VERSION 5.8 ;
BUSBITCHARS "[]" ;
DIVIDERCHAR "/" ;
UNITS
    DATABASE MICRONS 1000 ;
END UNITS

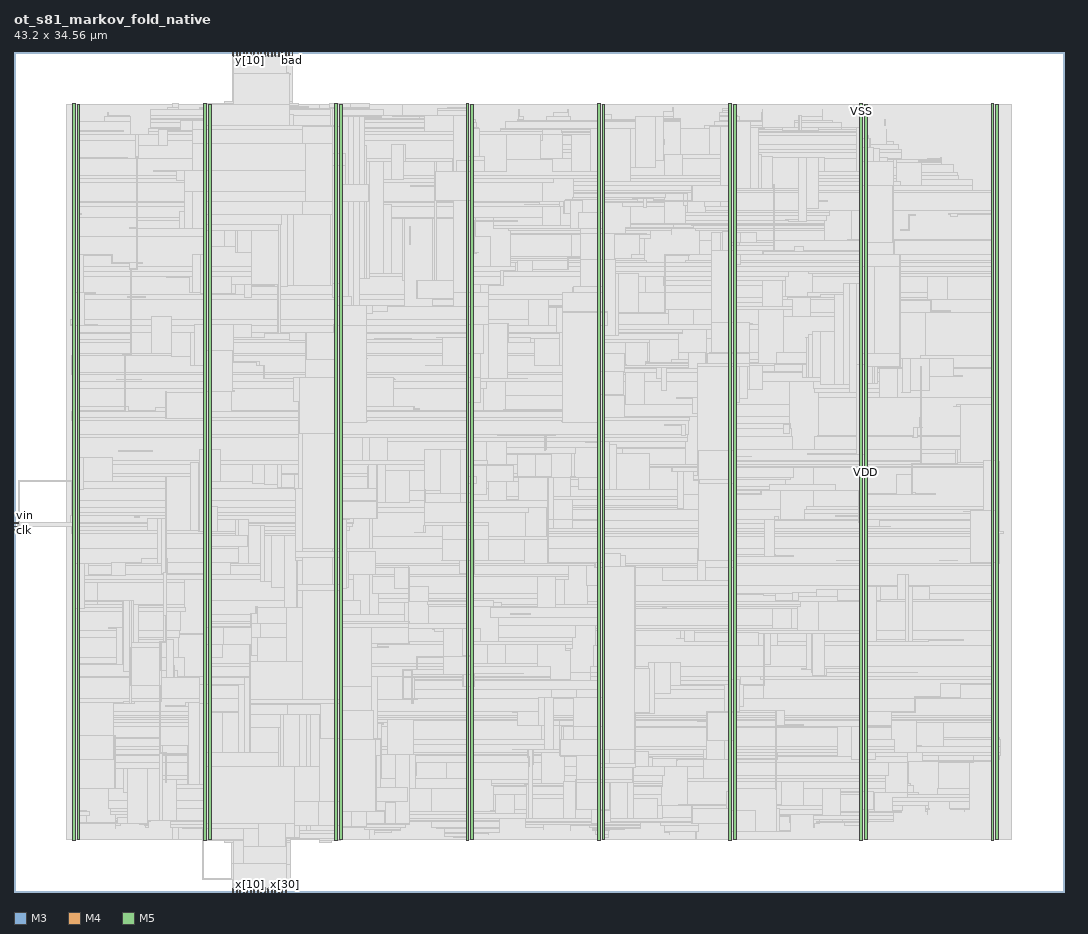
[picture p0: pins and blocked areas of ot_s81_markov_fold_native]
MACRO ot_s81_markov_fold_native
  FOREIGN ot_s81_markov_fold_native 0 0 ;
  CLASS BLOCK ;
  SIZE 43.2 BY 34.56 ;
  PIN bad
    DIRECTION OUTPUT ;
    USE SIGNAL ;
    PORT
      LAYER M3 ;
        RECT  11.448 34.416 11.466 34.56 ;
    END
  END bad
  PIN clk
    DIRECTION INPUT ;
    USE SIGNAL ;
    PORT
      LAYER M4 ;
        RECT  0 14.88 0.192 14.904 ;
    END
  END clk
  PIN rst_n
    DIRECTION INPUT ;
    USE SIGNAL ;
    PORT
      LAYER M4 ;
        RECT  0 15.024 0.192 15.048 ;
    END
  END rst_n
  PIN vin
    DIRECTION INPUT ;
    USE SIGNAL ;
    PORT
      LAYER M4 ;
        RECT  0 15.168 0.192 15.192 ;
    END
  END vin
  PIN vout
    DIRECTION OUTPUT ;
    USE SIGNAL ;
    PORT
      LAYER M3 ;
        RECT  11.304 34.416 11.322 34.56 ;
    END
  END vout
  PIN x[0]
    DIRECTION INPUT ;
    USE SIGNAL ;
    PORT
      LAYER M3 ;
        RECT  9 0 9.018 0.144 ;
    END
  END x[0]
  PIN x[10]
    DIRECTION INPUT ;
    USE SIGNAL ;
    PORT
      LAYER M3 ;
        RECT  9.72 0 9.738 0.144 ;
    END
  END x[10]
  PIN x[11]
    DIRECTION INPUT ;
    USE SIGNAL ;
    PORT
      LAYER M5 ;
        RECT  9.744 0 9.768 0.192 ;
    END
  END x[11]
  PIN x[12]
    DIRECTION INPUT ;
    USE SIGNAL ;
    PORT
      LAYER M3 ;
        RECT  9.864 0 9.882 0.144 ;
    END
  END x[12]
  PIN x[13]
    DIRECTION INPUT ;
    USE SIGNAL ;
    PORT
      LAYER M5 ;
        RECT  9.888 0 9.912 0.192 ;
    END
  END x[13]
  PIN x[14]
    DIRECTION INPUT ;
    USE SIGNAL ;
    PORT
      LAYER M3 ;
        RECT  10.008 0 10.026 0.144 ;
    END
  END x[14]
  PIN x[15]
    DIRECTION INPUT ;
    USE SIGNAL ;
    PORT
      LAYER M5 ;
        RECT  10.032 0 10.056 0.192 ;
    END
  END x[15]
  PIN x[16]
    DIRECTION INPUT ;
    USE SIGNAL ;
    PORT
      LAYER M3 ;
        RECT  10.152 0 10.17 0.144 ;
    END
  END x[16]
  PIN x[17]
    DIRECTION INPUT ;
    USE SIGNAL ;
    PORT
      LAYER M5 ;
        RECT  10.176 0 10.2 0.192 ;
    END
  END x[17]
  PIN x[18]
    DIRECTION INPUT ;
    USE SIGNAL ;
    PORT
      LAYER M3 ;
        RECT  10.296 0 10.314 0.144 ;
    END
  END x[18]
  PIN x[19]
    DIRECTION INPUT ;
    USE SIGNAL ;
    PORT
      LAYER M5 ;
        RECT  10.32 0 10.344 0.192 ;
    END
  END x[19]
  PIN x[1]
    DIRECTION INPUT ;
    USE SIGNAL ;
    PORT
      LAYER M5 ;
        RECT  9.024 0 9.048 0.192 ;
    END
  END x[1]
  PIN x[20]
    DIRECTION INPUT ;
    USE SIGNAL ;
    PORT
      LAYER M3 ;
        RECT  10.44 0 10.458 0.144 ;
    END
  END x[20]
  PIN x[21]
    DIRECTION INPUT ;
    USE SIGNAL ;
    PORT
      LAYER M5 ;
        RECT  10.464 0 10.488 0.192 ;
    END
  END x[21]
  PIN x[22]
    DIRECTION INPUT ;
    USE SIGNAL ;
    PORT
      LAYER M3 ;
        RECT  10.584 0 10.602 0.144 ;
    END
  END x[22]
  PIN x[23]
    DIRECTION INPUT ;
    USE SIGNAL ;
    PORT
      LAYER M5 ;
        RECT  10.608 0 10.632 0.192 ;
    END
  END x[23]
  PIN x[24]
    DIRECTION INPUT ;
    USE SIGNAL ;
    PORT
      LAYER M3 ;
        RECT  10.728 0 10.746 0.144 ;
    END
  END x[24]
  PIN x[25]
    DIRECTION INPUT ;
    USE SIGNAL ;
    PORT
      LAYER M5 ;
        RECT  10.752 0 10.776 0.192 ;
    END
  END x[25]
  PIN x[26]
    DIRECTION INPUT ;
    USE SIGNAL ;
    PORT
      LAYER M3 ;
        RECT  10.872 0 10.89 0.144 ;
    END
  END x[26]
  PIN x[27]
    DIRECTION INPUT ;
    USE SIGNAL ;
    PORT
      LAYER M5 ;
        RECT  10.896 0 10.92 0.192 ;
    END
  END x[27]
  PIN x[28]
    DIRECTION INPUT ;
    USE SIGNAL ;
    PORT
      LAYER M3 ;
        RECT  11.016 0 11.034 0.144 ;
    END
  END x[28]
  PIN x[29]
    DIRECTION INPUT ;
    USE SIGNAL ;
    PORT
      LAYER M5 ;
        RECT  11.04 0 11.064 0.192 ;
    END
  END x[29]
  PIN x[2]
    DIRECTION INPUT ;
    USE SIGNAL ;
    PORT
      LAYER M3 ;
        RECT  9.144 0 9.162 0.144 ;
    END
  END x[2]
  PIN x[30]
    DIRECTION INPUT ;
    USE SIGNAL ;
    PORT
      LAYER M3 ;
        RECT  11.16 0 11.178 0.144 ;
    END
  END x[30]
  PIN x[31]
    DIRECTION INPUT ;
    USE SIGNAL ;
    PORT
      LAYER M5 ;
        RECT  11.184 0 11.208 0.192 ;
    END
  END x[31]
  PIN x[3]
    DIRECTION INPUT ;
    USE SIGNAL ;
    PORT
      LAYER M5 ;
        RECT  9.168 0 9.192 0.192 ;
    END
  END x[3]
  PIN x[4]
    DIRECTION INPUT ;
    USE SIGNAL ;
    PORT
      LAYER M3 ;
        RECT  9.288 0 9.306 0.144 ;
    END
  END x[4]
  PIN x[5]
    DIRECTION INPUT ;
    USE SIGNAL ;
    PORT
      LAYER M5 ;
        RECT  9.312 0 9.336 0.192 ;
    END
  END x[5]
  PIN x[6]
    DIRECTION INPUT ;
    USE SIGNAL ;
    PORT
      LAYER M3 ;
        RECT  9.432 0 9.45 0.144 ;
    END
  END x[6]
  PIN x[7]
    DIRECTION INPUT ;
    USE SIGNAL ;
    PORT
      LAYER M5 ;
        RECT  9.456 0 9.48 0.192 ;
    END
  END x[7]
  PIN x[8]
    DIRECTION INPUT ;
    USE SIGNAL ;
    PORT
      LAYER M3 ;
        RECT  9.576 0 9.594 0.144 ;
    END
  END x[8]
  PIN x[9]
    DIRECTION INPUT ;
    USE SIGNAL ;
    PORT
      LAYER M5 ;
        RECT  9.6 0 9.624 0.192 ;
    END
  END x[9]
  PIN y[0]
    DIRECTION OUTPUT ;
    USE SIGNAL ;
    PORT
      LAYER M3 ;
        RECT  9 34.416 9.018 34.56 ;
    END
  END y[0]
  PIN y[10]
    DIRECTION OUTPUT ;
    USE SIGNAL ;
    PORT
      LAYER M3 ;
        RECT  9.72 34.416 9.738 34.56 ;
    END
  END y[10]
  PIN y[11]
    DIRECTION OUTPUT ;
    USE SIGNAL ;
    PORT
      LAYER M5 ;
        RECT  9.744 34.368 9.768 34.56 ;
    END
  END y[11]
  PIN y[12]
    DIRECTION OUTPUT ;
    USE SIGNAL ;
    PORT
      LAYER M3 ;
        RECT  9.864 34.416 9.882 34.56 ;
    END
  END y[12]
  PIN y[13]
    DIRECTION OUTPUT ;
    USE SIGNAL ;
    PORT
      LAYER M5 ;
        RECT  9.888 34.368 9.912 34.56 ;
    END
  END y[13]
  PIN y[14]
    DIRECTION OUTPUT ;
    USE SIGNAL ;
    PORT
      LAYER M3 ;
        RECT  10.008 34.416 10.026 34.56 ;
    END
  END y[14]
  PIN y[15]
    DIRECTION OUTPUT ;
    USE SIGNAL ;
    PORT
      LAYER M5 ;
        RECT  10.032 34.368 10.056 34.56 ;
    END
  END y[15]
  PIN y[16]
    DIRECTION OUTPUT ;
    USE SIGNAL ;
    PORT
      LAYER M3 ;
        RECT  10.152 34.416 10.17 34.56 ;
    END
  END y[16]
  PIN y[17]
    DIRECTION OUTPUT ;
    USE SIGNAL ;
    PORT
      LAYER M5 ;
        RECT  10.176 34.368 10.2 34.56 ;
    END
  END y[17]
  PIN y[18]
    DIRECTION OUTPUT ;
    USE SIGNAL ;
    PORT
      LAYER M3 ;
        RECT  10.296 34.416 10.314 34.56 ;
    END
  END y[18]
  PIN y[19]
    DIRECTION OUTPUT ;
    USE SIGNAL ;
    PORT
      LAYER M5 ;
        RECT  10.32 34.368 10.344 34.56 ;
    END
  END y[19]
  PIN y[1]
    DIRECTION OUTPUT ;
    USE SIGNAL ;
    PORT
      LAYER M5 ;
        RECT  9.024 34.368 9.048 34.56 ;
    END
  END y[1]
  PIN y[20]
    DIRECTION OUTPUT ;
    USE SIGNAL ;
    PORT
      LAYER M3 ;
        RECT  10.44 34.416 10.458 34.56 ;
    END
  END y[20]
  PIN y[21]
    DIRECTION OUTPUT ;
    USE SIGNAL ;
    PORT
      LAYER M5 ;
        RECT  10.464 34.368 10.488 34.56 ;
    END
  END y[21]
  PIN y[22]
    DIRECTION OUTPUT ;
    USE SIGNAL ;
    PORT
      LAYER M3 ;
        RECT  10.584 34.416 10.602 34.56 ;
    END
  END y[22]
  PIN y[23]
    DIRECTION OUTPUT ;
    USE SIGNAL ;
    PORT
      LAYER M5 ;
        RECT  10.608 34.368 10.632 34.56 ;
    END
  END y[23]
  PIN y[24]
    DIRECTION OUTPUT ;
    USE SIGNAL ;
    PORT
      LAYER M3 ;
        RECT  10.728 34.416 10.746 34.56 ;
    END
  END y[24]
  PIN y[25]
    DIRECTION OUTPUT ;
    USE SIGNAL ;
    PORT
      LAYER M5 ;
        RECT  10.752 34.368 10.776 34.56 ;
    END
  END y[25]
  PIN y[26]
    DIRECTION OUTPUT ;
    USE SIGNAL ;
    PORT
      LAYER M3 ;
        RECT  10.872 34.416 10.89 34.56 ;
    END
  END y[26]
  PIN y[27]
    DIRECTION OUTPUT ;
    USE SIGNAL ;
    PORT
      LAYER M5 ;
        RECT  10.896 34.368 10.92 34.56 ;
    END
  END y[27]
  PIN y[28]
    DIRECTION OUTPUT ;
    USE SIGNAL ;
    PORT
      LAYER M3 ;
        RECT  11.016 34.416 11.034 34.56 ;
    END
  END y[28]
  PIN y[29]
    DIRECTION OUTPUT ;
    USE SIGNAL ;
    PORT
      LAYER M5 ;
        RECT  11.04 34.368 11.064 34.56 ;
    END
  END y[29]
  PIN y[2]
    DIRECTION OUTPUT ;
    USE SIGNAL ;
    PORT
      LAYER M3 ;
        RECT  9.144 34.416 9.162 34.56 ;
    END
  END y[2]
  PIN y[30]
    DIRECTION OUTPUT ;
    USE SIGNAL ;
    PORT
      LAYER M3 ;
        RECT  11.16 34.416 11.178 34.56 ;
    END
  END y[30]
  PIN y[31]
    DIRECTION OUTPUT ;
    USE SIGNAL ;
    PORT
      LAYER M5 ;
        RECT  11.184 34.368 11.208 34.56 ;
    END
  END y[31]
  PIN y[3]
    DIRECTION OUTPUT ;
    USE SIGNAL ;
    PORT
      LAYER M5 ;
        RECT  9.168 34.368 9.192 34.56 ;
    END
  END y[3]
  PIN y[4]
    DIRECTION OUTPUT ;
    USE SIGNAL ;
    PORT
      LAYER M3 ;
        RECT  9.288 34.416 9.306 34.56 ;
    END
  END y[4]
  PIN y[5]
    DIRECTION OUTPUT ;
    USE SIGNAL ;
    PORT
      LAYER M5 ;
        RECT  9.312 34.368 9.336 34.56 ;
    END
  END y[5]
  PIN y[6]
    DIRECTION OUTPUT ;
    USE SIGNAL ;
    PORT
      LAYER M3 ;
        RECT  9.432 34.416 9.45 34.56 ;
    END
  END y[6]
  PIN y[7]
    DIRECTION OUTPUT ;
    USE SIGNAL ;
    PORT
      LAYER M5 ;
        RECT  9.456 34.368 9.48 34.56 ;
    END
  END y[7]
  PIN y[8]
    DIRECTION OUTPUT ;
    USE SIGNAL ;
    PORT
      LAYER M3 ;
        RECT  9.576 34.416 9.594 34.56 ;
    END
  END y[8]
  PIN y[9]
    DIRECTION OUTPUT ;
    USE SIGNAL ;
    PORT
      LAYER M5 ;
        RECT  9.6 34.368 9.624 34.56 ;
    END
  END y[9]
  PIN VDD
    DIRECTION INOUT ;
    USE POWER ;
    PORT
      LAYER M5 ;
        RECT  40.392 2.151 40.512 32.409 ;
        RECT  34.992 2.151 35.112 32.409 ;
        RECT  29.592 2.151 29.712 32.409 ;
        RECT  24.192 2.151 24.312 32.409 ;
        RECT  18.792 2.151 18.912 32.409 ;
        RECT  13.392 2.151 13.512 32.409 ;
        RECT  7.992 2.151 8.112 32.409 ;
        RECT  2.592 2.151 2.712 32.409 ;
    END
  END VDD
  PIN VSS
    DIRECTION INOUT ;
    USE GROUND ;
    PORT
      LAYER M5 ;
        RECT  40.2 2.137 40.32 32.423 ;
        RECT  34.8 2.137 34.92 32.423 ;
        RECT  29.4 2.137 29.52 32.423 ;
        RECT  24 2.137 24.12 32.423 ;
        RECT  18.6 2.137 18.72 32.423 ;
        RECT  13.2 2.137 13.32 32.423 ;
        RECT  7.8 2.137 7.92 32.423 ;
        RECT  2.4 2.137 2.52 32.423 ;
    END
  END VSS
  # OT_OBS_CLOSED layer=M5 d_um=1.536 added=71
  OBS
    LAYER RVTN ;
     RECT  2.16 2.16 41.04 2.295 ;
     RECT  2.16 2.565 41.04 2.835 ;
     RECT  2.16 3.105 41.04 3.375 ;
     RECT  2.16 3.645 41.04 3.915 ;
     RECT  2.16 4.185 41.04 4.455 ;
     RECT  2.16 4.725 41.04 4.995 ;
     RECT  2.16 5.265 41.04 5.535 ;
     RECT  2.16 5.805 41.04 6.075 ;
     RECT  2.16 6.345 41.04 6.615 ;
     RECT  2.16 6.885 41.04 7.155 ;
     RECT  2.16 7.425 41.04 7.695 ;
     RECT  2.16 7.965 41.04 8.235 ;
     RECT  2.16 8.505 41.04 8.775 ;
     RECT  2.16 9.045 41.04 9.315 ;
     RECT  2.16 9.585 41.04 9.855 ;
     RECT  2.16 10.125 41.04 10.395 ;
     RECT  2.16 10.665 41.04 10.935 ;
     RECT  2.16 11.205 41.04 11.475 ;
     RECT  2.16 11.745 41.04 12.015 ;
     RECT  2.16 12.285 41.04 12.555 ;
     RECT  2.16 12.825 41.04 13.095 ;
     RECT  2.16 13.365 41.04 13.635 ;
     RECT  2.16 13.905 41.04 14.175 ;
     RECT  2.16 14.445 41.04 14.715 ;
     RECT  2.16 14.985 41.04 15.255 ;
     RECT  2.16 15.525 41.04 15.795 ;
     RECT  2.16 16.065 41.04 16.335 ;
     RECT  2.16 16.605 41.04 16.875 ;
     RECT  2.16 17.145 41.04 17.415 ;
     RECT  2.16 17.685 41.04 17.955 ;
     RECT  2.16 18.225 41.04 18.495 ;
     RECT  2.16 18.765 41.04 19.035 ;
     RECT  2.16 19.305 41.04 19.575 ;
     RECT  2.16 19.845 41.04 20.115 ;
     RECT  2.16 20.385 41.04 20.655 ;
     RECT  2.16 20.925 41.04 21.195 ;
     RECT  2.16 21.465 41.04 21.735 ;
     RECT  2.16 22.005 41.04 22.275 ;
     RECT  2.16 22.545 41.04 22.815 ;
     RECT  2.16 23.085 41.04 23.355 ;
     RECT  2.16 23.625 41.04 23.895 ;
     RECT  2.16 24.165 41.04 24.435 ;
     RECT  2.16 24.705 41.04 24.975 ;
     RECT  2.16 25.245 41.04 25.515 ;
     RECT  2.16 25.785 41.04 26.055 ;
     RECT  2.16 26.325 41.04 26.595 ;
     RECT  2.16 26.865 41.04 27.135 ;
     RECT  2.16 27.405 41.04 27.675 ;
     RECT  2.16 27.945 41.04 28.215 ;
     RECT  2.16 28.485 41.04 28.755 ;
     RECT  2.16 29.025 41.04 29.295 ;
     RECT  2.16 29.565 41.04 29.835 ;
     RECT  2.16 30.105 41.04 30.375 ;
     RECT  2.16 30.645 41.04 30.915 ;
     RECT  2.16 31.185 41.04 31.455 ;
     RECT  2.16 31.725 41.04 31.995 ;
     RECT  2.16 32.265 41.04 32.4 ;
    LAYER RVTP ;
     RECT  2.16 2.295 41.04 2.565 ;
     RECT  2.16 2.835 41.04 3.105 ;
     RECT  2.16 3.375 41.04 3.645 ;
     RECT  2.16 3.915 41.04 4.185 ;
     RECT  2.16 4.455 41.04 4.725 ;
     RECT  2.16 4.995 41.04 5.265 ;
     RECT  2.16 5.535 41.04 5.805 ;
     RECT  2.16 6.075 41.04 6.345 ;
     RECT  2.16 6.615 41.04 6.885 ;
     RECT  2.16 7.155 41.04 7.425 ;
     RECT  2.16 7.695 41.04 7.965 ;
     RECT  2.16 8.235 41.04 8.505 ;
     RECT  2.16 8.775 41.04 9.045 ;
     RECT  2.16 9.315 41.04 9.585 ;
     RECT  2.16 9.855 41.04 10.125 ;
     RECT  2.16 10.395 41.04 10.665 ;
     RECT  2.16 10.935 41.04 11.205 ;
     RECT  2.16 11.475 41.04 11.745 ;
     RECT  2.16 12.015 41.04 12.285 ;
     RECT  2.16 12.555 41.04 12.825 ;
     RECT  2.16 13.095 41.04 13.365 ;
     RECT  2.16 13.635 41.04 13.905 ;
     RECT  2.16 14.175 41.04 14.445 ;
     RECT  2.16 14.715 41.04 14.985 ;
     RECT  2.16 15.255 41.04 15.525 ;
     RECT  2.16 15.795 41.04 16.065 ;
     RECT  2.16 16.335 41.04 16.605 ;
     RECT  2.16 16.875 41.04 17.145 ;
     RECT  2.16 17.415 41.04 17.685 ;
     RECT  2.16 17.955 41.04 18.225 ;
     RECT  2.16 18.495 41.04 18.765 ;
     RECT  2.16 19.035 41.04 19.305 ;
     RECT  2.16 19.575 41.04 19.845 ;
     RECT  2.16 20.115 41.04 20.385 ;
     RECT  2.16 20.655 41.04 20.925 ;
     RECT  2.16 21.195 41.04 21.465 ;
     RECT  2.16 21.735 41.04 22.005 ;
     RECT  2.16 22.275 41.04 22.545 ;
     RECT  2.16 22.815 41.04 23.085 ;
     RECT  2.16 23.355 41.04 23.625 ;
     RECT  2.16 23.895 41.04 24.165 ;
     RECT  2.16 24.435 41.04 24.705 ;
     RECT  2.16 24.975 41.04 25.245 ;
     RECT  2.16 25.515 41.04 25.785 ;
     RECT  2.16 26.055 41.04 26.325 ;
     RECT  2.16 26.595 41.04 26.865 ;
     RECT  2.16 27.135 41.04 27.405 ;
     RECT  2.16 27.675 41.04 27.945 ;
     RECT  2.16 28.215 41.04 28.485 ;
     RECT  2.16 28.755 41.04 29.025 ;
     RECT  2.16 29.295 41.04 29.565 ;
     RECT  2.16 29.835 41.04 30.105 ;
     RECT  2.16 30.375 41.04 30.645 ;
     RECT  2.16 30.915 41.04 31.185 ;
     RECT  2.16 31.455 41.04 31.725 ;
     RECT  2.16 31.995 41.04 32.265 ;
    LAYER M1 ;
     RECT  2.16 2.151 41.04 32.409 ;
    LAYER M2 ;
     RECT  2.16 2.151 6.511 32.409 ;
     RECT  6.511 2.151 6.755 32.454 ;
     RECT  6.755 2.151 7.951 32.409 ;
     RECT  7.951 2.106 8.671 32.409 ;
     RECT  8.671 2.034 9.275 32.409 ;
     RECT  9.275 2.151 9.463 32.409 ;
     RECT  9.463 2.151 9.931 32.454 ;
     RECT  9.787 0.144 10.031 0.162 ;
     RECT  9.787 1.152 10.607 1.17 ;
     RECT  9.931 2.151 10.787 33.066 ;
     RECT  10.787 2.151 10.823 32.994 ;
     RECT  10.867 0.144 11.399 0.162 ;
     RECT  10.823 2.151 11.399 32.49 ;
     RECT  11.399 2.151 11.723 32.454 ;
     RECT  11.723 2.151 12.559 32.409 ;
     RECT  12.559 2.034 12.991 32.409 ;
     RECT  12.991 2.034 13.055 32.454 ;
     RECT  13.055 2.106 13.415 32.454 ;
     RECT  13.415 2.151 14.639 32.454 ;
     RECT  14.639 2.151 41.04 32.409 ;
    LAYER M3 ;
     RECT  9 0.108 11.178 0.139 ;
     RECT  9 0.139 11.394 1.147 ;
     RECT  8.964 1.147 11.394 2.029 ;
     RECT  7.776 0.523 7.794 2.101 ;
     RECT  8.676 2.029 11.394 2.101 ;
     RECT  12.564 2.029 13.05 2.101 ;
     RECT  7.776 2.101 11.394 2.191 ;
     RECT  12.564 2.101 13.41 2.191 ;
     RECT  18.615 2.143 18.705 2.227 ;
     RECT  24.015 2.143 24.105 2.227 ;
     RECT  18.072 2.227 18.705 2.263 ;
     RECT  24.015 2.227 24.462 2.371 ;
     RECT  2.415 2.143 2.505 2.413 ;
     RECT  7.776 2.191 13.41 2.413 ;
     RECT  17.712 2.263 18.705 2.413 ;
     RECT  19.512 2.371 19.53 2.413 ;
     RECT  29.415 2.143 29.505 2.413 ;
     RECT  34.815 2.143 34.905 2.413 ;
     RECT  40.215 2.143 40.305 2.413 ;
     RECT  14.832 2.371 14.85 2.461 ;
     RECT  17.712 2.413 19.53 2.461 ;
     RECT  26.964 2.371 26.982 2.461 ;
     RECT  26.784 2.461 26.982 2.497 ;
     RECT  28.044 2.191 28.062 2.497 ;
     RECT  14.832 2.461 15.534 2.533 ;
     RECT  23.94 2.371 24.462 2.533 ;
     RECT  14.832 2.533 15.894 2.569 ;
     RECT  23.796 2.533 24.498 2.569 ;
     RECT  7.776 2.413 13.497 2.605 ;
     RECT  17.712 2.461 19.962 2.605 ;
     RECT  23.796 2.569 25.11 2.605 ;
     RECT  6.948 2.605 13.497 2.641 ;
     RECT  14.436 2.569 15.894 2.641 ;
     RECT  17.388 2.605 19.962 2.641 ;
     RECT  21.78 2.569 21.798 2.641 ;
     RECT  23.796 2.605 25.794 2.641 ;
     RECT  4.176 2.605 4.194 2.731 ;
     RECT  5.4 2.641 5.526 2.731 ;
     RECT  22.896 2.533 22.914 2.731 ;
     RECT  23.688 2.641 25.794 2.731 ;
     RECT  26.784 2.497 28.17 2.731 ;
     RECT  34.815 2.413 35.097 2.731 ;
     RECT  5.364 2.731 5.526 2.767 ;
     RECT  6.444 2.641 16.11 2.767 ;
     RECT  21.06 2.641 21.798 2.767 ;
     RECT  22.896 2.731 25.794 2.767 ;
     RECT  32.904 2.641 32.922 2.803 ;
     RECT  2.415 2.413 2.697 2.827 ;
     RECT  21.06 2.767 25.794 2.839 ;
     RECT  26.604 2.731 28.17 2.839 ;
     RECT  29.415 2.413 29.697 2.839 ;
     RECT  31.932 2.491 31.95 2.839 ;
     RECT  34.164 2.731 35.097 2.839 ;
     RECT  34.092 2.839 35.097 2.875 ;
     RECT  4.176 2.731 4.374 2.911 ;
     RECT  5.148 2.767 5.526 2.911 ;
     RECT  6.444 2.767 16.254 2.911 ;
     RECT  17.172 2.641 19.962 2.911 ;
     RECT  21.06 2.839 28.17 2.911 ;
     RECT  34.092 2.875 35.154 2.911 ;
     RECT  4.176 2.911 5.598 2.923 ;
     RECT  6.444 2.911 19.962 2.923 ;
     RECT  29.088 2.839 29.697 3.001 ;
     RECT  30.744 2.731 31.122 3.001 ;
     RECT  32.904 2.803 33.138 3.001 ;
     RECT  34.092 2.911 36.198 3.001 ;
     RECT  4.176 2.923 19.962 3.029 ;
     RECT  21.06 2.911 28.314 3.109 ;
     RECT  29.088 3.001 31.122 3.109 ;
     RECT  31.896 2.839 31.95 3.109 ;
     RECT  32.904 3.001 36.198 3.137 ;
     RECT  2.415 2.827 2.97 3.145 ;
     RECT  20.592 3.109 28.314 3.145 ;
     RECT  29.088 3.109 31.95 3.145 ;
     RECT  4.176 3.029 19.818 3.181 ;
     RECT  20.592 3.145 31.95 3.181 ;
     RECT  32.904 3.137 33.246 3.181 ;
     RECT  34.02 3.137 36.198 3.271 ;
     RECT  2.415 3.145 3.114 3.299 ;
     RECT  3.96 3.181 19.818 3.299 ;
     RECT  34.02 3.271 36.522 3.299 ;
     RECT  37.584 3.181 37.602 3.307 ;
     RECT  2.415 3.299 2.97 3.335 ;
     RECT  36.144 3.299 36.522 3.343 ;
     RECT  19.62 3.299 19.818 3.371 ;
     RECT  39.096 3.307 39.114 3.379 ;
     RECT  20.592 3.181 33.246 3.389 ;
     RECT  37.512 3.307 37.602 3.403 ;
     RECT  3.96 3.299 16.218 3.451 ;
     RECT  38.52 3.379 39.33 3.451 ;
     RECT  36.144 3.343 36.558 3.541 ;
     RECT  37.512 3.403 37.638 3.541 ;
     RECT  27.36 3.389 33.246 3.569 ;
     RECT  27.36 3.569 31.59 3.605 ;
     RECT  36.144 3.541 37.638 3.721 ;
     RECT  38.484 3.451 39.33 3.721 ;
     RECT  3.888 3.451 16.218 3.773 ;
     RECT  36.144 3.721 39.33 3.875 ;
     RECT  19.728 3.371 19.818 3.991 ;
     RECT  20.592 3.389 26.622 3.991 ;
     RECT  34.02 3.299 35.406 3.991 ;
     RECT  36.756 3.875 39.33 4.019 ;
     RECT  33.984 3.991 35.406 4.075 ;
     RECT  36.756 4.019 37.206 4.109 ;
     RECT  3.888 3.773 15.75 4.261 ;
     RECT  17.172 3.299 18.897 4.261 ;
     RECT  32.472 3.569 33.246 4.261 ;
     RECT  33.984 4.075 35.874 4.261 ;
     RECT  38.016 4.019 39.33 4.262 ;
     RECT  16.74 4.261 18.897 4.301 ;
     RECT  19.728 3.991 26.622 4.351 ;
     RECT  17.316 4.301 18.897 4.379 ;
     RECT  36.756 4.109 37.026 4.379 ;
     RECT  19.728 4.351 26.694 4.387 ;
     RECT  19.656 4.387 26.694 4.451 ;
     RECT  36.756 4.379 36.882 4.451 ;
     RECT  27.72 3.605 31.59 4.531 ;
     RECT  32.472 4.261 35.874 4.531 ;
     RECT  22.608 4.451 26.694 4.541 ;
     RECT  17.784 4.379 18.897 4.621 ;
     RECT  19.656 4.451 21.69 4.621 ;
     RECT  27.72 4.531 35.874 4.685 ;
     RECT  3.78 4.261 15.75 4.801 ;
     RECT  22.644 4.541 26.694 4.801 ;
     RECT  29.415 4.685 35.874 4.801 ;
     RECT  22.644 4.801 26.766 5.161 ;
     RECT  27.72 4.685 28.386 5.161 ;
     RECT  3.492 4.801 15.75 5.341 ;
     RECT  16.524 4.801 16.542 5.341 ;
     RECT  17.784 4.621 21.69 5.341 ;
     RECT  29.415 4.801 35.982 5.341 ;
     RECT  36.756 4.451 36.81 5.341 ;
     RECT  38.052 4.262 39.33 5.341 ;
     RECT  40.215 2.413 40.497 5.431 ;
     RECT  22.644 5.161 28.386 5.575 ;
     RECT  3.492 5.341 15.786 5.608 ;
     RECT  16.524 5.341 21.69 5.608 ;
     RECT  29.415 5.341 36.81 5.611 ;
     RECT  38.052 5.341 39.474 5.611 ;
     RECT  40.215 5.431 40.554 5.611 ;
     RECT  22.5 5.575 28.386 5.639 ;
     RECT  3.492 5.608 21.69 5.645 ;
     RECT  16.416 5.645 21.69 5.737 ;
     RECT  22.5 5.639 22.806 5.737 ;
     RECT  29.415 5.611 40.59 5.741 ;
     RECT  2.415 3.335 2.697 5.845 ;
     RECT  3.492 5.645 15.354 5.845 ;
     RECT  23.724 5.639 28.386 5.881 ;
     RECT  29.415 5.741 36.234 5.881 ;
     RECT  2.415 5.845 15.354 5.999 ;
     RECT  23.724 5.881 36.234 5.999 ;
     RECT  37.116 5.741 40.59 5.999 ;
     RECT  37.116 5.999 37.35 6.035 ;
     RECT  16.416 5.737 22.806 6.071 ;
     RECT  16.416 6.071 22.626 6.269 ;
     RECT  34.74 5.999 36.234 6.269 ;
     RECT  38.232 5.999 40.59 6.269 ;
     RECT  38.232 6.269 40.554 6.341 ;
     RECT  23.724 5.999 33.93 6.763 ;
     RECT  34.74 6.269 36.09 6.763 ;
     RECT  22.428 6.269 22.626 6.811 ;
     RECT  23.724 6.763 36.09 6.811 ;
     RECT  3.492 5.999 15.354 6.817 ;
     RECT  3.456 6.817 15.354 6.961 ;
     RECT  37.116 6.035 37.134 6.961 ;
     RECT  38.232 6.341 40.497 6.961 ;
     RECT  16.416 6.269 21.69 7.051 ;
     RECT  22.428 6.811 36.09 7.051 ;
     RECT  37.116 6.961 40.497 7.051 ;
     RECT  3.42 6.961 15.354 7.087 ;
     RECT  16.416 7.051 40.497 7.087 ;
     RECT  2.415 5.999 2.697 7.159 ;
     RECT  3.42 7.087 40.497 7.159 ;
     RECT  2.415 7.159 40.497 7.259 ;
     RECT  2.415 7.259 22.194 7.421 ;
     RECT  2.415 7.421 22.122 7.961 ;
     RECT  23.148 7.259 40.497 7.961 ;
     RECT  16.488 7.961 22.122 8.311 ;
     RECT  23.148 7.961 29.898 8.311 ;
     RECT  16.488 8.311 29.898 8.699 ;
     RECT  16.488 8.699 22.914 8.735 ;
     RECT  30.852 7.961 40.497 8.743 ;
     RECT  2.415 7.961 15.678 8.815 ;
     RECT  16.488 8.735 22.086 8.815 ;
     RECT  23.724 8.699 29.898 8.851 ;
     RECT  30.708 8.743 40.497 8.851 ;
     RECT  2.415 8.815 22.086 8.879 ;
     RECT  7.815 8.879 22.086 9.275 ;
     RECT  23.724 8.851 40.497 9.275 ;
     RECT  7.815 9.275 21.546 9.419 ;
     RECT  2.415 8.879 7.002 9.653 ;
     RECT  22.896 8.735 22.914 9.931 ;
     RECT  22.68 9.931 22.914 10.021 ;
     RECT  23.832 9.275 40.497 10.157 ;
     RECT  7.815 9.419 19.494 10.201 ;
     RECT  20.232 9.419 21.546 10.201 ;
     RECT  22.68 10.021 22.986 10.201 ;
     RECT  7.815 10.201 22.986 10.319 ;
     RECT  2.415 9.653 6.75 10.471 ;
     RECT  19.944 10.319 22.986 10.471 ;
     RECT  2.415 10.471 6.822 10.741 ;
     RECT  23.94 10.157 40.497 10.769 ;
     RECT  7.815 10.319 19.206 10.859 ;
     RECT  23.94 10.769 32.238 10.859 ;
     RECT  23.94 10.859 31.194 10.967 ;
     RECT  19.944 10.471 23.094 10.975 ;
     RECT  23.94 10.967 24.786 10.975 ;
     RECT  7.815 10.859 18.897 11.039 ;
     RECT  7.815 11.039 16.29 11.129 ;
     RECT  19.944 10.975 24.786 11.281 ;
     RECT  7.815 11.129 16.074 11.399 ;
     RECT  2.415 10.741 6.858 11.551 ;
     RECT  25.524 10.967 31.194 11.677 ;
     RECT  32.004 10.859 32.238 11.677 ;
     RECT  2.415 11.551 7.074 11.705 ;
     RECT  19.62 11.281 24.786 11.705 ;
     RECT  25.524 11.677 32.238 11.749 ;
     RECT  17.064 11.039 18.897 11.755 ;
     RECT  19.62 11.705 21.546 11.755 ;
     RECT  22.284 11.705 24.786 11.813 ;
     RECT  17.064 11.755 21.546 11.821 ;
     RECT  23.58 11.813 24.786 11.821 ;
     RECT  25.524 11.749 32.346 11.821 ;
     RECT  2.415 11.705 7.002 11.849 ;
     RECT  15.012 11.399 16.074 11.911 ;
     RECT  23.58 11.821 32.346 11.947 ;
     RECT  33.12 10.769 40.497 11.947 ;
     RECT  7.815 11.399 14.274 11.975 ;
     RECT  15.012 11.911 16.218 12.091 ;
     RECT  16.992 11.821 21.546 12.091 ;
     RECT  15.012 12.091 21.546 12.289 ;
     RECT  23.58 11.947 40.497 12.595 ;
     RECT  2.415 11.849 2.697 12.721 ;
     RECT  3.42 11.849 7.002 12.721 ;
     RECT  2.415 12.721 7.002 12.865 ;
     RECT  7.815 11.975 13.986 12.865 ;
     RECT  22.284 11.813 22.662 12.865 ;
     RECT  14.76 12.289 21.546 12.991 ;
     RECT  22.284 12.865 22.806 12.991 ;
     RECT  2.415 12.865 13.986 13.051 ;
     RECT  14.76 12.991 22.806 13.051 ;
     RECT  2.415 13.051 22.806 13.441 ;
     RECT  23.544 12.595 40.497 13.441 ;
     RECT  2.415 13.441 40.497 13.531 ;
     RECT  2.415 13.531 40.554 14.135 ;
     RECT  14.76 14.135 40.554 14.639 ;
     RECT  21.924 14.639 40.554 14.731 ;
     RECT  2.415 14.135 13.662 14.755 ;
     RECT  21.924 14.731 40.698 14.819 ;
     RECT  2.376 14.755 13.662 14.881 ;
     RECT  21.924 14.819 40.554 14.945 ;
     RECT  2.376 14.881 13.806 15.019 ;
     RECT  2.304 15.019 13.806 15.025 ;
     RECT  2.304 15.025 13.914 15.151 ;
     RECT  2.304 15.151 13.986 15.163 ;
     RECT  2.268 15.163 13.986 15.215 ;
     RECT  22.968 14.945 40.554 15.287 ;
     RECT  32.4 15.287 40.554 15.323 ;
     RECT  2.304 15.215 13.986 15.485 ;
     RECT  32.508 15.323 40.554 15.557 ;
     RECT  2.376 15.485 13.986 15.601 ;
     RECT  14.76 14.639 21.042 15.601 ;
     RECT  32.544 15.557 40.554 15.719 ;
     RECT  22.968 15.287 31.554 15.755 ;
     RECT  22.968 15.755 27.522 15.821 ;
     RECT  2.376 15.601 21.186 15.835 ;
     RECT  21.924 14.945 22.194 15.835 ;
     RECT  32.616 15.719 40.554 15.863 ;
     RECT  22.968 15.821 27.45 15.899 ;
     RECT  2.376 15.835 22.194 16.097 ;
     RECT  20.268 16.097 22.194 16.141 ;
     RECT  22.968 15.899 27.378 16.141 ;
     RECT  20.268 16.141 27.378 16.259 ;
     RECT  28.296 15.755 31.554 16.501 ;
     RECT  28.296 16.501 31.662 16.555 ;
     RECT  2.376 16.097 19.53 16.589 ;
     RECT  22.896 16.259 27.378 16.681 ;
     RECT  28.116 16.555 31.662 16.681 ;
     RECT  22.896 16.681 31.734 16.951 ;
     RECT  22.896 16.951 31.95 17.041 ;
     RECT  22.896 17.041 32.058 17.069 ;
     RECT  20.268 16.259 22.122 17.075 ;
     RECT  22.896 17.069 23.094 17.105 ;
     RECT  2.415 16.589 19.53 17.221 ;
     RECT  20.268 17.075 20.718 17.221 ;
     RECT  24.015 17.069 32.058 17.455 ;
     RECT  32.904 15.863 40.554 17.455 ;
     RECT  24.015 17.455 40.554 17.501 ;
     RECT  2.415 17.221 20.718 17.609 ;
     RECT  25.02 17.501 40.554 17.609 ;
     RECT  28.692 17.609 40.554 17.717 ;
     RECT  2.415 17.609 19.494 17.753 ;
     RECT  28.692 17.717 40.497 17.753 ;
     RECT  20.268 17.609 20.718 17.995 ;
     RECT  21.456 17.075 22.122 17.995 ;
     RECT  20.268 17.995 22.122 18.031 ;
     RECT  22.932 17.105 23.058 18.031 ;
     RECT  28.836 17.753 40.497 18.221 ;
     RECT  24.015 17.501 24.297 18.265 ;
     RECT  25.02 17.609 27.63 18.265 ;
     RECT  20.268 18.031 23.094 18.301 ;
     RECT  24.015 18.265 27.63 18.301 ;
     RECT  15.372 17.753 19.458 18.535 ;
     RECT  20.268 18.301 27.63 18.535 ;
     RECT  2.415 17.753 14.346 18.697 ;
     RECT  15.372 18.535 27.702 18.697 ;
     RECT  28.944 18.221 32.022 18.725 ;
     RECT  32.94 18.221 40.497 18.725 ;
     RECT  33.048 18.725 40.497 18.797 ;
     RECT  2.415 18.697 27.702 18.841 ;
     RECT  28.944 18.725 31.986 19.076 ;
     RECT  28.944 19.076 31.95 19.265 ;
     RECT  2.415 18.841 27.738 19.381 ;
     RECT  2.376 19.381 27.774 19.535 ;
     RECT  25.128 19.535 27.774 19.543 ;
     RECT  28.944 19.265 31.914 19.543 ;
     RECT  2.376 19.535 24.297 19.769 ;
     RECT  2.415 19.769 24.297 19.805 ;
     RECT  20.16 19.805 24.297 19.841 ;
     RECT  25.128 19.543 31.914 20.075 ;
     RECT  33.084 18.797 40.497 20.345 ;
     RECT  20.232 19.841 24.297 20.425 ;
     RECT  25.128 20.075 25.146 20.425 ;
     RECT  33.084 20.345 35.622 20.551 ;
     RECT  32.94 20.551 35.622 20.695 ;
     RECT  2.415 19.805 19.314 20.731 ;
     RECT  2.415 20.731 19.422 21.001 ;
     RECT  20.232 20.425 25.146 21.001 ;
     RECT  25.92 20.075 31.914 21.001 ;
     RECT  32.904 20.695 35.622 21.001 ;
     RECT  2.415 21.001 25.146 21.271 ;
     RECT  2.376 21.271 25.146 21.355 ;
     RECT  25.92 21.001 35.622 21.355 ;
     RECT  2.376 21.355 35.622 21.389 ;
     RECT  25.128 21.389 35.622 21.541 ;
     RECT  36.36 20.345 40.497 21.541 ;
     RECT  25.128 21.541 40.497 21.569 ;
     RECT  25.128 21.569 36.45 21.659 ;
     RECT  25.992 21.659 36.45 21.677 ;
     RECT  25.128 21.659 25.218 21.695 ;
     RECT  25.992 21.677 36.342 21.725 ;
     RECT  25.992 21.725 30.618 21.803 ;
     RECT  25.992 21.803 26.154 21.839 ;
     RECT  27.072 21.803 30.618 21.929 ;
     RECT  2.376 21.389 24.297 22.073 ;
     RECT  37.296 21.569 40.497 22.073 ;
     RECT  2.415 22.073 24.297 22.171 ;
     RECT  25.128 21.695 25.146 22.171 ;
     RECT  31.356 21.725 36.342 22.199 ;
     RECT  27.324 21.929 30.618 22.205 ;
     RECT  2.415 22.171 25.146 22.621 ;
     RECT  26.064 21.839 26.154 22.621 ;
     RECT  2.415 22.621 26.154 22.711 ;
     RECT  27.324 22.205 27.342 22.711 ;
     RECT  2.415 22.711 27.342 22.981 ;
     RECT  2.415 22.981 27.486 23.009 ;
     RECT  2.415 23.009 22.482 23.032 ;
     RECT  23.292 23.009 27.486 23.161 ;
     RECT  28.476 22.205 30.618 23.161 ;
     RECT  2.415 23.032 22.338 23.315 ;
     RECT  2.415 23.315 21.15 23.317 ;
     RECT  23.292 23.161 30.618 23.351 ;
     RECT  2.34 23.317 21.15 23.549 ;
     RECT  31.68 22.199 36.342 23.693 ;
     RECT  23.292 23.351 26.946 23.819 ;
     RECT  32.76 23.693 36.342 23.827 ;
     RECT  37.512 22.073 40.497 23.827 ;
     RECT  27.936 23.351 30.618 23.971 ;
     RECT  31.68 23.693 32.022 23.971 ;
     RECT  21.996 23.315 22.338 24.061 ;
     RECT  23.292 23.819 25.794 24.061 ;
     RECT  26.568 23.819 26.946 24.089 ;
     RECT  27.936 23.971 32.022 24.089 ;
     RECT  27.936 24.089 30.798 24.241 ;
     RECT  31.608 24.089 32.022 24.359 ;
     RECT  32.76 23.827 40.497 24.365 ;
     RECT  2.415 23.549 21.15 24.367 ;
     RECT  21.996 24.061 25.794 24.367 ;
     RECT  26.784 24.089 26.946 24.475 ;
     RECT  27.684 24.241 30.798 24.475 ;
     RECT  32.76 24.365 37.566 24.475 ;
     RECT  31.608 24.359 31.842 24.512 ;
     RECT  2.415 24.367 25.794 24.601 ;
     RECT  32.652 24.475 37.566 24.665 ;
     RECT  26.784 24.475 30.798 24.943 ;
     RECT  26.712 24.943 30.798 25.141 ;
     RECT  31.608 24.512 31.734 25.141 ;
     RECT  2.415 24.601 25.974 25.321 ;
     RECT  26.712 25.141 31.734 25.321 ;
     RECT  32.832 24.665 37.566 25.321 ;
     RECT  38.412 24.365 40.497 25.321 ;
     RECT  32.832 25.321 40.497 25.447 ;
     RECT  2.415 25.321 31.878 25.519 ;
     RECT  32.688 25.447 40.497 25.519 ;
     RECT  2.415 25.519 40.497 25.745 ;
     RECT  20.448 25.745 40.497 25.889 ;
     RECT  20.448 25.889 26.01 25.979 ;
     RECT  27.612 25.889 40.497 25.979 ;
     RECT  20.448 25.979 25.938 26.045 ;
     RECT  26.784 25.889 26.802 26.087 ;
     RECT  20.448 26.045 24.534 26.141 ;
     RECT  25.416 26.045 25.938 26.249 ;
     RECT  27.756 25.979 40.497 26.249 ;
     RECT  23.868 26.141 24.534 26.285 ;
     RECT  28.188 26.249 40.497 26.789 ;
     RECT  34.308 26.789 40.497 26.861 ;
     RECT  25.74 26.249 25.938 26.905 ;
     RECT  2.415 25.745 19.602 26.969 ;
     RECT  20.448 26.141 22.95 27.031 ;
     RECT  23.868 26.285 24.297 27.031 ;
     RECT  25.74 26.905 26.19 27.031 ;
     RECT  20.448 27.031 24.297 27.061 ;
     RECT  20.448 27.061 24.354 27.101 ;
     RECT  20.448 27.101 24.297 27.211 ;
     RECT  25.164 27.031 26.19 27.211 ;
     RECT  27.036 27.031 27.054 27.211 ;
     RECT  28.188 26.789 33.354 27.211 ;
     RECT  20.34 27.211 24.297 27.301 ;
     RECT  25.164 27.211 27.054 27.301 ;
     RECT  28.044 27.211 33.354 27.307 ;
     RECT  25.164 27.301 27.126 27.329 ;
     RECT  27.936 27.307 33.354 27.409 ;
     RECT  19.728 27.301 24.297 27.437 ;
     RECT  25.344 27.329 27.126 27.481 ;
     RECT  27.864 27.409 33.354 27.481 ;
     RECT  25.344 27.481 33.354 27.509 ;
     RECT  27.612 27.509 33.354 27.643 ;
     RECT  2.415 26.969 18.99 27.751 ;
     RECT  19.728 27.437 21.762 27.751 ;
     RECT  27.612 27.643 33.426 27.841 ;
     RECT  27.612 27.841 33.534 27.977 ;
     RECT  28.44 27.977 33.534 28.021 ;
     RECT  34.452 26.861 40.497 28.021 ;
     RECT  2.415 27.751 21.762 28.183 ;
     RECT  22.5 27.437 24.297 28.183 ;
     RECT  25.344 27.509 26.766 28.219 ;
     RECT  27.612 27.977 27.702 28.255 ;
     RECT  2.415 28.183 24.297 28.381 ;
     RECT  25.02 28.219 26.766 28.381 ;
     RECT  2.415 28.381 26.766 28.409 ;
     RECT  22.644 28.409 26.766 28.412 ;
     RECT  22.68 28.412 26.766 28.481 ;
     RECT  22.968 28.481 26.766 28.561 ;
     RECT  22.968 28.561 26.802 28.589 ;
     RECT  23.04 28.589 26.802 28.723 ;
     RECT  27.54 28.255 27.702 28.723 ;
     RECT  23.04 28.723 27.702 28.759 ;
     RECT  28.44 28.021 40.497 28.759 ;
     RECT  23.04 28.759 40.497 28.859 ;
     RECT  23.04 28.859 39.438 29.057 ;
     RECT  2.415 28.409 21.762 29.191 ;
     RECT  23.04 29.057 36.486 29.219 ;
     RECT  37.332 29.057 39.438 29.327 ;
     RECT  2.415 29.191 22.194 29.335 ;
     RECT  23.04 29.219 36.306 29.335 ;
     RECT  2.415 29.335 36.306 29.489 ;
     RECT  37.332 29.327 38.862 29.489 ;
     RECT  37.332 29.489 38.826 29.597 ;
     RECT  37.332 29.597 38.646 29.939 ;
     RECT  37.332 29.939 38.142 29.995 ;
     RECT  37.188 29.995 38.142 30.065 ;
     RECT  2.415 29.489 26.766 30.173 ;
     RECT  37.584 30.065 38.142 30.173 ;
     RECT  27.504 29.489 36.306 30.181 ;
     RECT  38.124 30.173 38.142 30.209 ;
     RECT  22.572 30.173 26.766 30.427 ;
     RECT  27.504 30.181 36.522 30.427 ;
     RECT  22.572 30.427 36.522 30.569 ;
     RECT  22.572 30.569 36.378 30.749 ;
     RECT  35.892 30.749 36.198 30.875 ;
     RECT  2.415 30.173 21.654 30.919 ;
     RECT  22.572 30.749 35.154 31.109 ;
     RECT  2.415 30.919 21.762 31.181 ;
     RECT  22.572 31.109 35.097 31.261 ;
     RECT  5.544 31.181 21.762 31.289 ;
     RECT  22.536 31.261 35.097 31.289 ;
     RECT  28.404 31.289 35.097 31.379 ;
     RECT  35.892 30.875 35.91 31.379 ;
     RECT  20.016 31.289 21.762 31.387 ;
     RECT  22.536 31.289 27.414 31.387 ;
     RECT  5.544 31.289 19.134 31.415 ;
     RECT  20.016 31.387 27.414 31.415 ;
     RECT  28.404 31.379 30.87 31.415 ;
     RECT  5.616 31.415 19.134 31.421 ;
     RECT  5.616 31.421 19.098 31.451 ;
     RECT  28.404 31.415 30.798 31.523 ;
     RECT  5.616 31.451 19.026 31.649 ;
     RECT  32.112 31.379 34.038 31.649 ;
     RECT  2.415 31.181 4.806 31.685 ;
     RECT  28.8 31.523 30.798 31.685 ;
     RECT  20.232 31.415 27.414 31.721 ;
     RECT  20.7 31.721 27.414 31.757 ;
     RECT  29.016 31.685 30.798 31.757 ;
     RECT  32.112 31.649 33.678 31.757 ;
     RECT  5.616 31.649 18.99 31.793 ;
     RECT  20.7 31.757 20.97 31.793 ;
     RECT  24.015 31.757 27.414 31.793 ;
     RECT  35.82 31.531 35.838 31.793 ;
     RECT  5.616 31.793 18.897 31.805 ;
     RECT  25.596 31.793 27.414 31.829 ;
     RECT  3.708 31.685 4.806 31.919 ;
     RECT  20.772 31.793 20.97 31.919 ;
     RECT  21.924 31.757 22.878 31.919 ;
     RECT  25.596 31.829 27.126 31.919 ;
     RECT  29.016 31.757 29.862 31.919 ;
     RECT  32.328 31.757 33.282 31.919 ;
     RECT  3.852 31.919 4.734 31.955 ;
     RECT  5.616 31.805 16.686 31.955 ;
     RECT  29.016 31.919 29.754 31.955 ;
     RECT  32.328 31.919 32.346 31.955 ;
     RECT  24.015 31.793 24.57 31.991 ;
     RECT  3.852 31.955 3.87 32.063 ;
     RECT  22.212 31.919 22.806 32.063 ;
     RECT  29.016 31.955 29.697 32.063 ;
     RECT  30.744 31.757 30.798 32.063 ;
     RECT  26.712 31.919 27.126 32.099 ;
     RECT  2.415 31.685 2.697 32.147 ;
     RECT  17.424 31.805 18.897 32.147 ;
     RECT  24.015 31.991 24.297 32.147 ;
     RECT  29.16 32.063 29.697 32.147 ;
     RECT  34.815 31.379 35.097 32.147 ;
     RECT  40.215 28.859 40.497 32.147 ;
     RECT  5.616 31.955 15.21 32.189 ;
     RECT  20.772 31.919 20.79 32.189 ;
     RECT  22.788 32.063 22.806 32.189 ;
     RECT  30.78 32.063 30.798 32.189 ;
     RECT  33.264 31.919 33.282 32.189 ;
     RECT  7.632 32.189 14.634 32.225 ;
     RECT  17.424 32.147 18.705 32.225 ;
     RECT  29.16 32.147 29.505 32.225 ;
     RECT  6.3 32.189 6.75 32.261 ;
     RECT  7.632 32.225 12.114 32.261 ;
     RECT  12.996 32.225 14.634 32.261 ;
     RECT  17.82 32.225 18.705 32.261 ;
     RECT  17.82 32.261 17.838 32.297 ;
     RECT  27.108 32.099 27.126 32.297 ;
     RECT  7.815 32.261 12.114 32.333 ;
     RECT  7.815 32.333 11.718 32.369 ;
     RECT  15.984 31.955 16.002 32.369 ;
     RECT  2.415 32.147 2.505 32.417 ;
     RECT  7.815 32.369 7.905 32.417 ;
     RECT  18.615 32.261 18.705 32.417 ;
     RECT  24.015 32.147 24.105 32.417 ;
     RECT  29.415 32.225 29.505 32.417 ;
     RECT  34.815 32.147 34.905 32.417 ;
     RECT  40.215 32.147 40.305 32.417 ;
     RECT  6.516 32.261 6.75 32.459 ;
     RECT  8.676 32.369 11.718 32.459 ;
     RECT  12.996 32.261 13.842 32.459 ;
     RECT  14.616 32.261 14.634 32.459 ;
     RECT  8.676 32.459 11.466 32.525 ;
     RECT  9 32.525 11.466 34.428 ;
    LAYER M4 ;
     RECT  0.156 14.88 0.227 15.192 ;
     RECT  0.181 16.896 2.365 16.92 ;
     RECT  0.227 15.024 2.408 15.192 ;
     RECT  2.365 16.56 2.408 16.92 ;
     RECT  2.329 23.328 2.408 23.352 ;
     RECT  2.408 2.148 2.512 32.412 ;
     RECT  2.512 2.418 2.704 32.142 ;
     RECT  2.704 27.888 2.765 27.912 ;
     RECT  2.704 16.56 2.873 17.88 ;
     RECT  2.704 24.624 2.873 26.232 ;
     RECT  2.704 11.664 2.915 11.976 ;
     RECT  2.704 13.008 3.053 13.512 ;
     RECT  2.873 24.624 3.341 24.648 ;
     RECT  2.704 23.328 3.449 23.352 ;
     RECT  3.053 13.008 4.021 13.032 ;
     RECT  2.873 26.208 4.021 26.232 ;
     RECT  2.873 16.896 4.061 17.88 ;
     RECT  4.021 25.872 4.061 26.232 ;
     RECT  2.704 5.856 4.069 5.88 ;
     RECT  4.069 5.856 4.076 6.456 ;
     RECT  3.769 4.272 4.117 4.296 ;
     RECT  4.076 5.424 4.117 6.456 ;
     RECT  4.117 4.272 4.156 6.456 ;
     RECT  4.156 4.272 4.163 6.36 ;
     RECT  2.704 9.36 4.237 9.384 ;
     RECT  3.877 10.848 4.237 10.872 ;
     RECT  2.704 2.832 4.273 2.856 ;
     RECT  4.237 9.36 4.453 10.872 ;
     RECT  2.915 11.952 4.453 11.976 ;
     RECT  3.877 7.776 4.489 7.8 ;
     RECT  4.453 9.36 4.489 11.976 ;
     RECT  2.704 31.296 4.493 31.32 ;
     RECT  4.163 4.272 4.525 5.064 ;
     RECT  2.704 19.968 4.549 19.992 ;
     RECT  4.021 13.008 4.601 13.56 ;
     RECT  4.273 2.832 4.669 3.048 ;
     RECT  4.525 4.08 4.669 5.064 ;
     RECT  2.704 30.192 4.673 30.216 ;
     RECT  4.549 19.776 4.709 19.992 ;
     RECT  4.061 25.872 4.751 25.896 ;
     RECT  4.489 7.776 4.769 7.848 ;
     RECT  4.489 9.072 4.769 11.976 ;
     RECT  4.453 22.128 4.789 22.152 ;
     RECT  4.769 7.776 4.835 11.976 ;
     RECT  4.789 22.128 4.835 23.016 ;
     RECT  4.835 7.776 4.853 9.096 ;
     RECT  4.835 10.272 4.925 11.976 ;
     RECT  4.853 7.776 4.961 7.848 ;
     RECT  4.741 27.312 5.029 27.336 ;
     RECT  4.751 25.632 5.075 25.896 ;
     RECT  4.993 30.24 5.113 31.176 ;
     RECT  4.925 10.272 5.141 11.832 ;
     RECT  4.957 15.408 5.177 15.432 ;
     RECT  4.601 13.536 5.245 13.56 ;
     RECT  4.237 21.072 5.249 21.096 ;
     RECT  5.075 25.872 5.285 25.896 ;
     RECT  4.669 24.48 5.429 24.504 ;
     RECT  4.669 2.832 5.501 5.064 ;
     RECT  4.835 22.176 5.677 23.016 ;
     RECT  4.309 18.144 5.681 18.168 ;
     RECT  4.709 19.776 5.821 19.8 ;
     RECT  5.245 13.536 5.893 13.704 ;
     RECT  5.497 14.88 5.893 15.384 ;
     RECT  5.113 30.72 5.929 31.176 ;
     RECT  5.501 2.928 5.989 5.064 ;
     RECT  4.163 6.336 5.989 6.36 ;
     RECT  4.961 7.824 5.996 7.848 ;
     RECT  4.853 9.072 5.996 9.096 ;
     RECT  5.989 2.928 6.005 6.36 ;
     RECT  5.893 13.536 6.081 15.384 ;
     RECT  5.996 7.824 6.083 9.096 ;
     RECT  6.005 2.928 6.113 6.024 ;
     RECT  5.141 11.808 6.133 11.832 ;
     RECT  6.133 11.376 6.179 11.832 ;
     RECT  6.081 13.104 6.217 15.384 ;
     RECT  4.061 16.896 6.217 17.112 ;
     RECT  6.179 11.376 6.22 11.4 ;
     RECT  5.821 19.776 6.229 19.944 ;
     RECT  6.083 8.832 6.289 9.096 ;
     RECT  5.141 10.272 6.289 10.392 ;
     RECT  6.217 13.104 6.293 17.112 ;
     RECT  6.293 13.104 6.329 13.704 ;
     RECT  5.929 30.72 6.329 31.368 ;
     RECT  5.677 22.176 6.469 23.688 ;
     RECT  6.469 22.032 6.473 23.688 ;
     RECT  6.289 8.832 6.545 10.392 ;
     RECT  6.545 8.832 6.617 9.336 ;
     RECT  5.749 29.664 6.685 29.688 ;
     RECT  6.113 2.928 6.689 4.632 ;
     RECT  6.617 8.832 6.725 9.096 ;
     RECT  5.029 27.312 6.793 27.624 ;
     RECT  6.329 31.344 6.865 31.368 ;
     RECT  6.793 27.312 6.997 28.008 ;
     RECT  6.685 29.28 6.997 29.688 ;
     RECT  6.253 7.632 7.045 7.656 ;
     RECT  6.689 4.416 7.153 4.632 ;
     RECT  6.113 5.712 7.153 6.024 ;
     RECT  7.153 4.416 7.189 6.024 ;
     RECT  7.045 7.632 7.189 7.8 ;
     RECT  6.289 25.296 7.225 25.32 ;
     RECT  6.293 14.88 7.261 17.112 ;
     RECT  6.473 22.032 7.261 23.016 ;
     RECT  7.225 24.672 7.333 25.32 ;
     RECT  6.997 27.312 7.333 29.688 ;
     RECT  6.865 31.344 7.333 31.752 ;
     RECT  7.261 21.648 7.441 23.016 ;
     RECT  7.261 14.88 7.585 17.688 ;
     RECT  7.189 4.416 7.621 7.8 ;
     RECT  6.725 8.832 7.621 8.856 ;
     RECT  7.585 14.832 7.621 17.688 ;
     RECT  7.333 24.672 7.693 26.232 ;
     RECT  6.689 2.928 7.808 3.432 ;
     RECT  7.621 4.416 7.808 8.856 ;
     RECT  6.793 10.608 7.808 10.632 ;
     RECT  6.329 13.104 7.808 13.56 ;
     RECT  7.621 14.832 7.808 18.216 ;
     RECT  6.229 19.488 7.808 20.568 ;
     RECT  7.441 21.648 7.808 23.352 ;
     RECT  7.693 24.624 7.808 26.232 ;
     RECT  7.333 27.312 7.808 31.752 ;
     RECT  7.808 2.148 7.912 32.412 ;
     RECT  7.912 2.418 8.104 32.412 ;
     RECT  8.104 14.832 8.381 15.864 ;
     RECT  8.104 16.896 8.489 18.216 ;
     RECT  8.104 2.64 8.579 7.368 ;
     RECT  8.104 9.648 8.597 10.92 ;
     RECT  8.597 10.176 8.627 10.92 ;
     RECT  8.104 26.544 8.665 32.412 ;
     RECT  8.104 13.056 8.921 13.56 ;
     RECT  7.765 0.528 8.953 0.552 ;
     RECT  8.104 19.776 8.957 20.616 ;
     RECT  8.104 24.624 8.957 25.32 ;
     RECT  8.104 21.792 9.029 23.352 ;
     RECT  8.957 20.592 9.052 20.616 ;
     RECT  8.953 0.528 9.059 1.176 ;
     RECT  8.381 14.832 9.097 15.336 ;
     RECT  8.957 24.624 9.097 24.984 ;
     RECT  8.665 26.544 9.097 32.52 ;
     RECT  9.059 0.528 9.169 0.6 ;
     RECT  9.097 26.304 9.203 32.52 ;
     RECT  8.579 2.736 9.241 7.368 ;
     RECT  8.104 8.496 9.241 8.52 ;
     RECT  8.921 13.536 9.241 13.56 ;
     RECT  9.097 14.64 9.241 15.336 ;
     RECT  9.169 0.48 9.313 0.6 ;
     RECT  9.313 0.192 9.347 0.6 ;
     RECT  9.241 2.736 9.493 8.52 ;
     RECT  9.097 24.576 9.493 24.984 ;
     RECT  9.241 13.536 9.641 15.336 ;
     RECT  9.493 2.736 9.701 8.808 ;
     RECT  8.627 10.416 9.701 10.92 ;
     RECT  9.493 33.648 9.733 33.672 ;
     RECT  9.701 2.736 9.74 10.92 ;
     RECT  9.347 0.192 9.779 0.552 ;
     RECT  9.029 22.8 9.785 23.352 ;
     RECT  9.493 24.48 9.785 24.984 ;
     RECT  8.489 16.896 9.817 17.592 ;
     RECT  9.203 26.304 9.821 31.944 ;
     RECT  9.74 2.736 9.953 11.448 ;
     RECT  9.029 21.792 9.961 21.816 ;
     RECT  9.953 2.736 10.037 11.736 ;
     RECT  9.785 24.912 10.069 24.984 ;
     RECT  9.821 26.304 10.069 29.208 ;
     RECT  9.961 21.648 10.109 21.816 ;
     RECT  9.641 13.536 10.141 15.096 ;
     RECT  10.037 2.736 10.181 11.016 ;
     RECT  9.779 0.528 10.211 0.552 ;
     RECT  9.133 18.816 10.217 18.84 ;
     RECT  10.109 21.648 10.249 21.672 ;
     RECT  10.249 21.12 10.289 21.672 ;
     RECT  9.785 22.8 10.289 23.016 ;
     RECT  9.817 16.8 10.321 17.592 ;
     RECT  10.141 12.768 10.325 15.096 ;
     RECT  9.745 1.728 10.393 1.752 ;
     RECT  10.181 2.736 10.393 10.92 ;
     RECT  9.733 33.072 10.577 33.672 ;
     RECT  10.325 12.768 10.609 14.664 ;
     RECT  10.577 33.648 10.741 33.672 ;
     RECT  10.289 22.992 10.825 23.016 ;
     RECT  10.069 24.912 10.825 29.208 ;
     RECT  10.321 16.752 10.861 17.592 ;
     RECT  10.825 22.992 10.861 29.208 ;
     RECT  9.821 30.192 10.861 31.944 ;
     RECT  10.861 22.992 10.885 31.944 ;
     RECT  10.885 22.992 10.973 31.992 ;
     RECT  10.393 1.728 10.979 10.92 ;
     RECT  10.861 16.656 11.009 17.592 ;
     RECT  10.979 1.728 11.081 9.192 ;
     RECT  10.979 10.272 11.149 10.92 ;
     RECT  10.609 12.528 11.149 14.664 ;
     RECT  10.973 24.912 11.261 31.992 ;
     RECT  10.741 33.648 11.294 33.72 ;
     RECT  10.973 22.992 11.329 23.016 ;
     RECT  11.294 33.648 11.377 33.672 ;
     RECT  10.289 21.12 11.509 21.144 ;
     RECT  11.261 24.96 11.513 31.992 ;
     RECT  11.009 16.656 11.557 17.16 ;
     RECT  11.509 20.208 11.596 21.144 ;
     RECT  11.149 10.272 11.617 14.664 ;
     RECT  11.557 16.56 11.747 17.16 ;
     RECT  11.081 2.256 11.765 9.192 ;
     RECT  11.596 21.12 11.773 21.144 ;
     RECT  11.833 18.816 11.917 18.84 ;
     RECT  11.747 16.608 11.945 17.16 ;
     RECT  11.945 16.608 11.981 17.064 ;
     RECT  11.329 22.704 11.989 23.016 ;
     RECT  11.617 10.272 12.017 15.432 ;
     RECT  11.989 21.504 12.035 23.016 ;
     RECT  11.765 2.544 12.049 9.192 ;
     RECT  12.017 10.272 12.049 10.536 ;
     RECT  12.049 2.544 12.197 10.536 ;
     RECT  12.017 11.808 12.445 15.432 ;
     RECT  11.513 24.96 13.021 31.944 ;
     RECT  12.197 9.312 13.093 10.536 ;
     RECT  13.021 24.96 13.093 32.232 ;
     RECT  12.035 21.504 13.165 22.584 ;
     RECT  12.197 2.544 13.208 7.944 ;
     RECT  13.093 9.312 13.208 10.728 ;
     RECT  12.445 11.808 13.208 15.576 ;
     RECT  11.981 16.608 13.208 17.016 ;
     RECT  12.193 18.768 13.208 18.792 ;
     RECT  12.625 20.4 13.208 20.424 ;
     RECT  13.165 21.504 13.208 23.352 ;
     RECT  13.093 24.48 13.208 32.232 ;
     RECT  13.208 2.148 13.312 32.412 ;
     RECT  13.312 2.418 13.504 32.142 ;
     RECT  13.504 12.48 13.673 15.336 ;
     RECT  13.673 12.528 13.745 13.992 ;
     RECT  13.504 21.936 13.781 31.896 ;
     RECT  13.673 15.312 13.817 15.336 ;
     RECT  13.504 2.688 13.889 8.76 ;
     RECT  13.781 23.328 13.948 31.896 ;
     RECT  13.948 23.808 14.213 31.896 ;
     RECT  13.504 20.4 14.321 20.424 ;
     RECT  14.213 25.248 14.429 31.896 ;
     RECT  13.889 2.688 14.501 3.672 ;
     RECT  14.429 25.248 14.501 30.696 ;
     RECT  13.504 19.344 14.531 19.368 ;
     RECT  13.781 21.936 14.531 21.96 ;
     RECT  13.504 16.608 14.533 17.112 ;
     RECT  13.504 10.08 14.605 10.872 ;
     RECT  14.533 16.608 14.605 17.496 ;
     RECT  14.501 25.248 14.609 30.072 ;
     RECT  13.889 4.656 14.677 8.76 ;
     RECT  14.605 9.936 14.723 10.872 ;
     RECT  14.213 23.808 14.753 24.12 ;
     RECT  13.745 13.056 14.861 13.992 ;
     RECT  14.876 15.36 14.917 15.384 ;
     RECT  14.605 16.608 14.917 17.592 ;
     RECT  14.917 15.36 14.963 17.592 ;
     RECT  14.677 4.656 14.969 8.856 ;
     RECT  14.723 10.08 14.969 10.728 ;
     RECT  14.969 4.656 15.107 6.936 ;
     RECT  14.429 31.872 15.113 31.896 ;
     RECT  14.609 25.44 15.185 30.072 ;
     RECT  15.107 6.912 15.221 6.936 ;
     RECT  14.963 16.032 15.293 17.592 ;
     RECT  14.753 23.904 15.365 24.12 ;
     RECT  14.969 10.08 15.401 10.104 ;
     RECT  15.185 29.328 15.541 30.072 ;
     RECT  15.185 25.44 15.545 28.296 ;
     RECT  14.785 21.072 15.548 21.096 ;
     RECT  15.548 21.072 15.635 21.144 ;
     RECT  14.861 13.056 15.649 13.368 ;
     RECT  14.501 2.832 15.685 3.672 ;
     RECT  15.107 4.656 15.685 5.64 ;
     RECT  15.635 21.072 15.689 21.096 ;
     RECT  14.969 7.92 15.973 8.856 ;
     RECT  15.545 25.44 15.973 27.72 ;
     RECT  15.973 7.92 16.013 9.144 ;
     RECT  15.541 29.328 16.013 30.744 ;
     RECT  15.365 24.096 16.081 24.12 ;
     RECT  15.973 25.152 16.081 27.72 ;
     RECT  16.013 30.048 16.121 30.744 ;
     RECT  15.649 12.48 16.213 13.368 ;
     RECT  15.685 2.832 16.252 5.64 ;
     RECT  16.009 10.224 16.259 10.248 ;
     RECT  16.213 11.952 16.259 13.368 ;
     RECT  16.252 2.832 16.265 2.856 ;
     RECT  15.293 16.032 16.265 17.352 ;
     RECT  16.013 7.92 16.357 7.944 ;
     RECT  14.821 22.752 16.373 22.776 ;
     RECT  15.589 19.968 16.441 19.992 ;
     RECT  16.357 7.776 16.444 7.944 ;
     RECT  16.441 19.872 16.481 19.992 ;
     RECT  16.252 4.272 16.517 5.64 ;
     RECT  16.013 9.12 16.549 9.144 ;
     RECT  16.444 7.92 16.589 7.944 ;
     RECT  16.549 9.12 16.589 9.672 ;
     RECT  16.481 19.872 16.697 19.896 ;
     RECT  16.477 14.784 16.844 14.808 ;
     RECT  15.577 31.92 16.873 31.944 ;
     RECT  16.265 16.512 16.909 17.352 ;
     RECT  16.844 14.784 16.913 15.096 ;
     RECT  16.913 15.072 16.931 15.096 ;
     RECT  16.259 11.952 17.057 12.552 ;
     RECT  16.081 24.096 17.237 27.72 ;
     RECT  17.237 25.152 17.297 27.72 ;
     RECT  16.297 29.04 17.297 29.064 ;
     RECT  17.233 10.8 17.305 10.824 ;
     RECT  17.297 25.152 17.317 29.064 ;
     RECT  16.121 30.048 17.317 30.072 ;
     RECT  17.317 25.152 17.381 30.072 ;
     RECT  16.909 16.512 17.557 18.216 ;
     RECT  16.945 21.648 17.629 21.672 ;
     RECT  17.377 22.8 17.629 22.824 ;
     RECT  16.589 9.648 17.653 9.672 ;
     RECT  17.653 8.976 17.665 9.672 ;
     RECT  17.305 10.704 17.665 10.824 ;
     RECT  17.381 29.376 18.061 30.072 ;
     RECT  18.061 29.376 18.097 30.168 ;
     RECT  16.873 31.296 18.097 31.944 ;
     RECT  17.605 13.632 18.349 13.656 ;
     RECT  17.557 15.984 18.373 18.216 ;
     RECT  17.665 8.976 18.469 10.824 ;
     RECT  16.517 4.272 18.608 4.68 ;
     RECT  18.469 8.448 18.608 10.824 ;
     RECT  17.057 11.952 18.608 11.976 ;
     RECT  18.349 13.104 18.608 13.656 ;
     RECT  18.373 15.312 18.608 18.216 ;
     RECT  17.629 21.648 18.608 22.824 ;
     RECT  17.237 24.096 18.608 24.12 ;
     RECT  17.381 25.152 18.608 27.72 ;
     RECT  18.097 29.376 18.608 31.944 ;
     RECT  18.608 2.148 18.712 32.412 ;
     RECT  18.712 2.418 18.904 32.142 ;
     RECT  18.904 8.448 18.965 9 ;
     RECT  18.904 13.104 18.965 15.192 ;
     RECT  18.904 26.256 18.965 27.624 ;
     RECT  18.965 26.256 19.037 26.328 ;
     RECT  19.037 26.304 19.109 26.328 ;
     RECT  18.904 29.664 19.145 31.416 ;
     RECT  18.904 20.16 19.187 24.984 ;
     RECT  18.904 16.368 19.433 17.544 ;
     RECT  18.965 13.632 19.523 15.192 ;
     RECT  19.187 21.12 19.523 24.984 ;
     RECT  18.904 11.76 19.721 11.976 ;
     RECT  19.523 24.96 20.005 24.984 ;
     RECT  19.721 11.76 20.045 11.928 ;
     RECT  20.005 24.96 20.153 25.56 ;
     RECT  19.145 29.664 20.261 31.176 ;
     RECT  19.523 21.12 20.297 23.4 ;
     RECT  20.297 22.608 20.333 23.4 ;
     RECT  19.433 16.896 20.549 17.544 ;
     RECT  20.153 25.536 20.617 25.56 ;
     RECT  20.509 7.392 20.725 7.416 ;
     RECT  20.617 25.536 20.725 25.896 ;
     RECT  18.965 27.6 20.729 27.624 ;
     RECT  20.549 16.896 20.761 17.064 ;
     RECT  18.965 8.976 20.945 9 ;
     RECT  19.523 13.632 21.013 14.52 ;
     RECT  18.904 3.024 21.085 3.24 ;
     RECT  21.013 4.416 21.085 4.44 ;
     RECT  20.509 5.856 21.116 5.88 ;
     RECT  20.297 21.12 21.125 21.144 ;
     RECT  21.085 3.024 21.157 4.44 ;
     RECT  21.116 5.52 21.157 5.88 ;
     RECT  20.437 11.424 21.233 11.448 ;
     RECT  20.333 22.608 21.269 22.824 ;
     RECT  21.157 3.024 21.341 5.88 ;
     RECT  20.725 25.536 21.341 25.992 ;
     RECT  21.341 5.232 21.377 5.88 ;
     RECT  21.269 22.608 21.409 22.776 ;
     RECT  20.725 6.864 21.589 7.416 ;
     RECT  21.013 28.272 21.625 28.296 ;
     RECT  20.261 30.144 21.665 31.176 ;
     RECT  19.897 18.768 21.829 18.792 ;
     RECT  21.377 5.856 21.841 5.88 ;
     RECT  21.589 6.864 21.841 7.992 ;
     RECT  21.829 18.192 21.916 18.792 ;
     RECT  21.013 13.536 21.949 14.52 ;
     RECT  20.761 16.128 21.949 17.064 ;
     RECT  21.949 13.536 21.989 17.064 ;
     RECT  21.665 30.144 22.165 30.168 ;
     RECT  21.841 5.856 22.205 7.992 ;
     RECT  21.989 15.312 22.205 17.064 ;
     RECT  21.916 18.768 22.277 18.792 ;
     RECT  22.205 5.856 22.453 6.84 ;
     RECT  21.409 21.648 22.453 22.776 ;
     RECT  21.625 28.272 22.453 28.392 ;
     RECT  22.453 5.616 22.521 6.84 ;
     RECT  22.021 24.096 22.549 24.12 ;
     RECT  22.453 21.648 22.595 23.016 ;
     RECT  21.341 3.024 22.597 3.864 ;
     RECT  22.453 28.224 22.597 28.392 ;
     RECT  22.525 19.344 22.609 19.368 ;
     RECT  22.597 27.936 22.669 28.392 ;
     RECT  21.341 25.632 22.777 25.992 ;
     RECT  22.777 25.632 22.817 26.136 ;
     RECT  22.669 27.936 22.885 28.44 ;
     RECT  22.165 29.664 22.921 30.168 ;
     RECT  21.665 31.152 22.921 31.176 ;
     RECT  22.549 24.096 22.988 24.648 ;
     RECT  22.595 22.992 23.029 23.016 ;
     RECT  22.988 24.096 23.029 24.888 ;
     RECT  22.597 3.024 23.084 4.536 ;
     RECT  22.205 17.04 23.209 17.064 ;
     RECT  22.885 27.312 23.389 28.44 ;
     RECT  22.921 29.664 23.713 31.176 ;
     RECT  23.084 3.024 23.749 4.632 ;
     RECT  22.521 5.616 23.893 5.64 ;
     RECT  21.989 13.536 23.893 13.56 ;
     RECT  23.029 22.992 23.893 24.888 ;
     RECT  22.817 26.112 23.893 26.136 ;
     RECT  23.749 2.832 24.008 4.632 ;
     RECT  23.893 5.616 24.008 5.784 ;
     RECT  22.521 6.816 24.008 6.84 ;
     RECT  22.205 7.968 24.008 7.992 ;
     RECT  22.885 9.024 24.008 9.048 ;
     RECT  23.893 13.344 24.008 13.56 ;
     RECT  22.205 15.312 24.008 15.336 ;
     RECT  23.209 16.56 24.008 17.064 ;
     RECT  23.497 18.48 24.008 18.504 ;
     RECT  23.893 20.592 24.008 20.616 ;
     RECT  22.595 21.648 24.008 21.672 ;
     RECT  23.893 22.992 24.008 26.136 ;
     RECT  23.389 27.312 24.008 28.488 ;
     RECT  23.713 29.664 24.008 31.416 ;
     RECT  24.008 2.148 24.112 32.412 ;
     RECT  24.112 2.418 24.304 32.142 ;
     RECT  24.304 8.976 24.473 9.048 ;
     RECT  24.304 16.56 24.515 18.504 ;
     RECT  24.304 2.88 24.545 7.368 ;
     RECT  24.304 22.896 24.761 26.04 ;
     RECT  24.515 16.56 24.797 18.408 ;
     RECT  24.761 22.896 24.869 25.464 ;
     RECT  24.304 13.344 24.941 13.944 ;
     RECT  24.304 20.496 25.091 21.384 ;
     RECT  24.304 10.8 25.157 10.824 ;
     RECT  24.941 13.344 25.157 13.848 ;
     RECT  24.545 3.024 25.229 7.368 ;
     RECT  25.091 21.36 25.229 21.384 ;
     RECT  25.229 7.344 25.297 7.368 ;
     RECT  24.304 29.232 25.373 31.416 ;
     RECT  25.229 3.024 25.475 5.784 ;
     RECT  25.475 5.136 25.571 5.784 ;
     RECT  25.484 11.28 25.571 11.304 ;
     RECT  25.297 7.344 25.585 7.992 ;
     RECT  24.473 8.976 25.585 9 ;
     RECT  25.373 29.808 25.585 31.416 ;
     RECT  25.441 28.512 25.657 28.536 ;
     RECT  24.869 23.856 25.697 25.464 ;
     RECT  25.657 28.416 25.909 28.536 ;
     RECT  24.304 27.072 26.021 27.096 ;
     RECT  25.909 28.176 26.021 28.536 ;
     RECT  25.571 5.184 26.093 5.784 ;
     RECT  25.585 7.344 26.101 9 ;
     RECT  26.101 7.344 26.125 9.192 ;
     RECT  24.797 16.56 26.129 18.024 ;
     RECT  26.093 5.184 26.273 5.544 ;
     RECT  26.021 28.416 26.309 28.536 ;
     RECT  26.125 7.344 26.345 9.432 ;
     RECT  25.585 29.808 26.381 31.896 ;
     RECT  25.475 3.024 26.489 3.864 ;
     RECT  26.449 21.12 26.629 21.576 ;
     RECT  26.489 3.024 26.669 3.576 ;
     RECT  25.157 13.344 26.701 13.368 ;
     RECT  26.381 30.096 26.705 31.896 ;
     RECT  26.705 30.096 26.741 31.752 ;
     RECT  25.697 23.856 26.819 24.648 ;
     RECT  26.665 11.664 26.849 11.688 ;
     RECT  26.629 20.64 26.849 21.576 ;
     RECT  26.345 8.16 26.993 9.432 ;
     RECT  26.273 5.184 27.245 5.496 ;
     RECT  27.245 5.424 27.281 5.496 ;
     RECT  26.129 16.56 27.313 17.448 ;
     RECT  27.241 10.416 27.421 10.44 ;
     RECT  26.993 8.496 27.425 9.432 ;
     RECT  26.741 30.336 27.425 31.704 ;
     RECT  26.773 19.2 27.457 19.224 ;
     RECT  27.313 15.792 27.533 17.448 ;
     RECT  27.421 10.416 27.601 10.776 ;
     RECT  27.457 18.768 27.641 19.224 ;
     RECT  26.849 21.552 27.745 21.576 ;
     RECT  26.773 26.208 27.785 26.232 ;
     RECT  26.669 3.072 27.877 3.576 ;
     RECT  26.309 28.416 27.877 28.44 ;
     RECT  27.241 20.304 27.925 20.328 ;
     RECT  27.877 2.832 27.929 3.576 ;
     RECT  26.881 27.312 27.965 27.336 ;
     RECT  27.601 10.32 28.001 10.776 ;
     RECT  26.701 12.816 28.105 13.368 ;
     RECT  27.925 19.68 28.141 20.328 ;
     RECT  27.929 2.832 28.145 3.384 ;
     RECT  28.145 2.88 28.253 3.384 ;
     RECT  27.877 28.416 28.429 29.064 ;
     RECT  28.105 12.816 28.453 14.088 ;
     RECT  28.141 19.68 28.465 20.424 ;
     RECT  27.745 21.552 28.465 22.2 ;
     RECT  27.281 5.472 28.501 5.496 ;
     RECT  28.105 7.008 28.501 7.032 ;
     RECT  28.465 19.68 28.501 22.2 ;
     RECT  27.425 30.336 28.609 31.416 ;
     RECT  27.533 16.368 28.825 17.448 ;
     RECT  28.693 26.352 29.077 27.144 ;
     RECT  28.429 28.224 29.077 29.064 ;
     RECT  28.609 30.336 29.077 31.512 ;
     RECT  29.077 25.824 29.149 27.144 ;
     RECT  28.825 16.368 29.185 18.216 ;
     RECT  28.501 5.472 29.221 7.416 ;
     RECT  27.425 8.496 29.221 8.52 ;
     RECT  28.253 2.88 29.329 3.336 ;
     RECT  29.329 2.88 29.408 4.152 ;
     RECT  29.221 5.472 29.408 8.52 ;
     RECT  28.001 10.32 29.408 10.68 ;
     RECT  28.453 12.816 29.408 14.136 ;
     RECT  29.185 15.504 29.408 18.216 ;
     RECT  28.501 19.68 29.408 22.776 ;
     RECT  26.819 23.952 29.408 24.648 ;
     RECT  29.149 25.824 29.408 27.192 ;
     RECT  29.077 28.224 29.408 31.512 ;
     RECT  29.408 2.148 29.512 32.412 ;
     RECT  29.512 2.418 29.704 32.142 ;
     RECT  29.704 20.16 29.837 23.4 ;
     RECT  29.704 7.392 29.843 8.712 ;
     RECT  29.704 25.824 29.873 27.144 ;
     RECT  29.843 7.632 30.017 8.52 ;
     RECT  29.837 20.304 30.161 23.4 ;
     RECT  30.161 20.688 30.275 23.4 ;
     RECT  29.704 28.944 30.305 31.704 ;
     RECT  29.704 17.904 30.341 17.928 ;
     RECT  30.275 23.376 30.377 23.4 ;
     RECT  29.873 26.256 30.557 27.144 ;
     RECT  29.704 10.128 30.629 10.68 ;
     RECT  30.305 28.944 30.629 31.464 ;
     RECT  29.704 16.368 30.733 16.392 ;
     RECT  30.629 28.944 30.737 30.36 ;
     RECT  30.733 16.368 30.773 16.536 ;
     RECT  30.275 20.688 30.809 21.672 ;
     RECT  30.017 8.496 30.841 8.52 ;
     RECT  30.629 10.128 30.841 10.632 ;
     RECT  29.704 12.24 30.841 12.264 ;
     RECT  30.557 26.256 30.851 26.376 ;
     RECT  29.704 13.824 30.877 13.896 ;
     RECT  29.704 15.168 30.877 15.336 ;
     RECT  30.841 8.496 30.881 10.632 ;
     RECT  30.773 16.512 31.093 16.536 ;
     RECT  30.881 9.36 31.133 10.632 ;
     RECT  30.737 28.944 31.205 30.264 ;
     RECT  30.809 21.408 31.273 21.672 ;
     RECT  30.877 13.824 31.277 15.336 ;
     RECT  31.277 15.312 31.309 15.336 ;
     RECT  31.277 13.824 31.313 13.896 ;
     RECT  29.704 5.472 31.333 5.496 ;
     RECT  30.841 12.192 31.345 12.264 ;
     RECT  29.704 2.496 31.379 4.248 ;
     RECT  31.333 5.472 31.421 5.688 ;
     RECT  31.133 10.128 31.421 10.632 ;
     RECT  31.309 15.312 31.457 15.432 ;
     RECT  31.379 2.496 31.493 3.432 ;
     RECT  30.629 31.44 31.633 31.464 ;
     RECT  31.333 6.864 31.709 7.464 ;
     RECT  31.741 27.648 31.885 27.672 ;
     RECT  31.669 18.864 31.889 19.224 ;
     RECT  31.493 2.496 31.961 2.52 ;
     RECT  31.889 19.2 31.961 19.224 ;
     RECT  31.345 12 32.029 12.264 ;
     RECT  31.313 13.824 32.069 13.848 ;
     RECT  30.851 26.352 32.101 26.376 ;
     RECT  31.885 27.6 32.281 27.672 ;
     RECT  31.205 28.944 32.281 30.216 ;
     RECT  32.029 12 32.285 12.312 ;
     RECT  31.633 31.344 32.293 31.464 ;
     RECT  32.293 31.344 32.38 31.944 ;
     RECT  31.273 21.408 32.425 21.72 ;
     RECT  31.709 6.864 32.461 6.888 ;
     RECT  32.461 6.768 32.501 6.888 ;
     RECT  32.101 26.352 32.501 26.568 ;
     RECT  32.389 9.168 32.605 9.192 ;
     RECT  31.421 10.32 32.605 10.632 ;
     RECT  32.425 21.168 32.605 21.72 ;
     RECT  32.569 22.8 32.605 22.824 ;
     RECT  32.281 27.6 32.609 30.216 ;
     RECT  32.605 21.168 32.677 22.824 ;
     RECT  32.605 9.168 32.821 10.632 ;
     RECT  32.821 9.024 32.857 10.632 ;
     RECT  32.677 21.168 32.857 22.92 ;
     RECT  32.285 12.144 33.037 12.312 ;
     RECT  32.609 28.128 33.113 30.216 ;
     RECT  32.38 31.344 33.113 31.464 ;
     RECT  32.857 21.168 33.181 23.064 ;
     RECT  31.813 24.48 33.181 24.504 ;
     RECT  31.457 15.312 33.221 15.336 ;
     RECT  32.857 8.928 33.329 10.632 ;
     RECT  33.113 29.664 33.365 30.216 ;
     RECT  33.329 8.928 33.437 9.192 ;
     RECT  33.113 28.416 33.473 28.44 ;
     RECT  33.181 20.88 33.757 23.064 ;
     RECT  33.181 24.48 33.757 24.6 ;
     RECT  31.093 16.512 33.797 16.776 ;
     RECT  31.421 5.568 33.865 5.592 ;
     RECT  32.501 6.768 33.865 6.792 ;
     RECT  33.037 12.144 33.901 12.456 ;
     RECT  33.757 20.88 34.117 24.6 ;
     RECT  34.117 20.88 34.369 25.032 ;
     RECT  33.865 5.568 34.477 6.792 ;
     RECT  34.369 20.544 34.645 25.032 ;
     RECT  33.365 29.664 34.657 30.168 ;
     RECT  33.113 31.44 34.657 31.464 ;
     RECT  33.793 15.456 34.765 15.48 ;
     RECT  33.797 16.512 34.765 16.536 ;
     RECT  33.037 2.88 34.808 2.904 ;
     RECT  34.009 4.128 34.808 4.152 ;
     RECT  34.477 5.472 34.808 6.792 ;
     RECT  33.437 9.024 34.808 9.192 ;
     RECT  33.329 10.32 34.808 10.632 ;
     RECT  33.901 12 34.808 12.456 ;
     RECT  33.829 13.632 34.808 13.656 ;
     RECT  34.765 15.216 34.808 16.536 ;
     RECT  32.641 18 34.808 18.024 ;
     RECT  34.645 20.4 34.808 25.032 ;
     RECT  32.501 26.352 34.808 26.376 ;
     RECT  34.657 29.664 34.808 31.464 ;
     RECT  34.808 2.148 34.912 32.412 ;
     RECT  34.912 2.418 35.104 32.142 ;
     RECT  35.104 20.88 35.129 23.352 ;
     RECT  35.104 2.88 35.165 4.104 ;
     RECT  35.104 28.896 35.219 30.984 ;
     RECT  35.129 20.928 35.309 23.352 ;
     RECT  35.165 3.408 35.389 4.104 ;
     RECT  35.104 24.336 35.411 26.808 ;
     RECT  35.309 20.928 35.417 23.064 ;
     RECT  35.104 5.472 35.453 5.736 ;
     RECT  35.104 10.32 35.489 12.552 ;
     RECT  35.417 20.928 35.525 22.584 ;
     RECT  35.104 15.024 35.597 15.336 ;
     RECT  35.219 28.896 35.597 30.6 ;
     RECT  35.489 12 35.669 12.552 ;
     RECT  35.411 25.68 35.813 26.808 ;
     RECT  35.597 28.896 35.957 30.216 ;
     RECT  35.597 15.024 36.065 15.048 ;
     RECT  35.104 6.864 36.101 7.416 ;
     RECT  35.957 28.896 36.179 30.12 ;
     RECT  35.813 26.208 36.217 26.808 ;
     RECT  35.104 16.368 36.313 16.392 ;
     RECT  36.179 29.808 36.317 30.12 ;
     RECT  35.669 12.048 36.349 12.552 ;
     RECT  36.217 26.208 36.467 26.232 ;
     RECT  36.529 20.544 36.565 20.568 ;
     RECT  35.525 21.6 36.565 21.96 ;
     RECT  35.489 10.32 36.673 10.392 ;
     RECT  36.349 12.048 36.673 13.08 ;
     RECT  35.453 5.568 36.781 5.736 ;
     RECT  36.673 10.32 36.785 13.08 ;
     RECT  36.493 27.216 36.817 27.24 ;
     RECT  36.817 27.216 36.857 27.864 ;
     RECT  36.565 20.544 36.893 21.96 ;
     RECT  36.313 16.368 36.925 17.16 ;
     RECT  36.785 10.32 36.965 12.552 ;
     RECT  36.925 16.368 36.965 17.64 ;
     RECT  36.961 18.72 36.997 18.744 ;
     RECT  35.389 4.08 37.037 4.104 ;
     RECT  36.101 7.392 37.069 7.416 ;
     RECT  36.965 16.368 37.073 16.44 ;
     RECT  36.857 27.84 37.073 27.864 ;
     RECT  37.069 7.392 37.109 8.04 ;
     RECT  35.104 9.024 37.181 9.048 ;
     RECT  36.997 18.72 37.181 19.128 ;
     RECT  36.317 30 37.217 30.12 ;
     RECT  37.181 19.104 37.244 19.128 ;
     RECT  36.965 17.616 37.285 17.64 ;
     RECT  37.244 19.104 37.331 19.512 ;
     RECT  36.781 5.376 37.361 5.736 ;
     RECT  37.331 19.104 37.397 19.128 ;
     RECT  36.965 10.32 37.613 10.392 ;
     RECT  37.501 3.408 37.649 3.432 ;
     RECT  36.965 12.048 37.685 12.552 ;
     RECT  36.893 20.64 37.685 21.96 ;
     RECT  35.411 24.336 37.717 24.36 ;
     RECT  37.717 23.904 37.757 24.36 ;
     RECT  37.073 16.368 37.901 16.392 ;
     RECT  37.109 8.016 38.113 8.04 ;
     RECT  37.217 30.096 38.153 30.12 ;
     RECT  38.437 27.888 38.545 27.912 ;
     RECT  37.757 23.904 38.549 23.928 ;
     RECT  37.685 21.216 38.657 21.96 ;
     RECT  37.285 17.616 38.725 18.024 ;
     RECT  38.653 19.968 38.797 19.992 ;
     RECT  38.077 13.632 38.801 13.656 ;
     RECT  38.545 27.792 38.801 27.912 ;
     RECT  38.725 17.616 38.837 18.216 ;
     RECT  38.689 25.728 38.837 25.752 ;
     RECT  38.837 17.664 38.941 18.216 ;
     RECT  38.797 19.968 38.941 20.04 ;
     RECT  38.113 8.016 38.945 8.568 ;
     RECT  38.657 21.216 39.017 21.24 ;
     RECT  37.613 10.368 39.053 10.392 ;
     RECT  39.085 15.648 39.349 15.672 ;
     RECT  39.349 14.784 39.877 15.672 ;
     RECT  39.877 14.784 40.069 16.536 ;
     RECT  37.361 5.376 40.208 5.4 ;
     RECT  38.945 8.544 40.208 8.568 ;
     RECT  37.685 12.048 40.208 12.264 ;
     RECT  39.349 13.584 40.208 13.608 ;
     RECT  40.069 14.736 40.208 16.68 ;
     RECT  38.941 17.664 40.208 20.04 ;
     RECT  38.801 27.888 40.208 27.912 ;
     RECT  40.208 2.148 40.312 32.412 ;
     RECT  40.312 2.418 40.504 32.142 ;
     RECT  40.504 14.736 40.709 14.76 ;
    LAYER M5 ;
     RECT  9.024 0.144 11.208 1.187 ;
     RECT  9.456 1.187 11.208 1.859 ;
     RECT  2.4 2.137 2.52 2.151 ;
     RECT  7.8 2.137 7.92 2.151 ;
     RECT  13.2 2.137 13.32 2.151 ;
     RECT  18.6 2.137 18.72 2.151 ;
     RECT  24 2.137 24.12 2.151 ;
     RECT  29.4 2.137 29.52 2.151 ;
     RECT  34.8 2.137 34.92 2.151 ;
     RECT  40.2 2.137 40.32 2.151 ;
     RECT  11.184 1.859 11.208 2.245 ;
     RECT  29.4 2.151 29.712 2.485 ;
     RECT  7.8 2.151 8.112 2.629 ;
     RECT  9.456 1.859 10.056 2.629 ;
     RECT  13.2 2.151 13.512 2.725 ;
     RECT  7.8 2.629 10.056 2.821 ;
     RECT  11.184 2.245 11.544 2.821 ;
     RECT  15.264 2.821 15.288 3.301 ;
     RECT  14.88 3.301 15.288 3.347 ;
     RECT  29.4 2.485 30.504 3.347 ;
     RECT  24 2.151 24.312 3.349 ;
     RECT  24 3.349 24.504 3.397 ;
     RECT  34.8 2.151 35.112 3.397 ;
     RECT  27.888 2.821 27.912 3.443 ;
     RECT  12.528 2.725 13.512 3.731 ;
     RECT  34.8 3.397 35.352 4.115 ;
     RECT  16.176 3.733 16.2 4.307 ;
     RECT  23.136 3.397 24.504 4.501 ;
     RECT  23.136 4.501 25.464 4.643 ;
     RECT  24 4.643 25.464 5.125 ;
     RECT  7.8 2.821 11.544 5.171 ;
     RECT  24 5.125 25.56 5.267 ;
     RECT  4.128 4.261 4.152 5.459 ;
     RECT  21.168 5.173 21.192 5.555 ;
     RECT  14.88 3.347 14.904 5.605 ;
     RECT  6.24 4.501 6.264 5.701 ;
     RECT  6 5.701 6.264 5.747 ;
     RECT  7.8 5.171 10.872 5.747 ;
     RECT  24 5.267 24.504 5.843 ;
     RECT  29.4 3.347 29.712 6.229 ;
     RECT  22.464 5.605 22.488 6.275 ;
     RECT  14.88 5.605 15.096 6.277 ;
     RECT  12.576 3.731 13.512 6.323 ;
     RECT  14.784 6.277 15.096 6.323 ;
     RECT  9.744 5.747 10.872 6.757 ;
     RECT  24 5.843 24.312 6.805 ;
     RECT  9.744 6.757 10.968 7.285 ;
     RECT  25.536 5.267 25.56 7.381 ;
     RECT  28.512 6.229 29.712 7.381 ;
     RECT  28.512 7.381 29.832 7.427 ;
     RECT  14.784 6.323 14.808 7.475 ;
     RECT  31.344 4.213 31.368 7.475 ;
     RECT  9.744 7.285 11.256 7.717 ;
     RECT  7.8 5.747 8.112 7.765 ;
     RECT  9.744 7.717 11.592 7.765 ;
     RECT  12.624 6.323 13.512 7.765 ;
     RECT  4.08 6.421 4.104 7.811 ;
     RECT  9.744 7.765 13.512 7.907 ;
     RECT  23.04 6.805 24.312 8.003 ;
     RECT  18.6 2.151 18.912 8.437 ;
     RECT  6 5.747 6.024 8.485 ;
     RECT  7.632 7.765 8.112 8.531 ;
     RECT  29.4 7.427 29.832 8.723 ;
     RECT  18.48 8.437 18.912 8.965 ;
     RECT  6 8.485 6.072 9.107 ;
     RECT  16.368 7.765 16.392 9.155 ;
     RECT  25.536 7.381 26.136 9.203 ;
     RECT  9.744 7.907 11.88 9.491 ;
     RECT  17.664 8.965 18.912 9.683 ;
     RECT  9.744 9.491 10.008 9.731 ;
     RECT  18.48 9.683 18.912 9.731 ;
     RECT  4.8 8.485 4.824 10.067 ;
     RECT  7.8 8.531 8.112 10.165 ;
     RECT  6 9.107 6.024 10.261 ;
     RECT  6 10.261 6.264 10.307 ;
     RECT  9.792 9.731 10.008 10.453 ;
     RECT  7.8 10.165 8.616 10.883 ;
     RECT  14.688 8.437 14.712 10.883 ;
     RECT  9.792 10.453 10.152 11.027 ;
     RECT  6.24 10.307 6.264 11.365 ;
     RECT  9.792 11.027 10.008 11.459 ;
     RECT  2.4 2.151 2.712 11.653 ;
     RECT  11.232 9.491 11.88 11.699 ;
     RECT  9.984 11.459 10.008 11.747 ;
     RECT  11.664 11.699 11.88 12.421 ;
     RECT  13.2 7.907 13.512 12.421 ;
     RECT  11.664 12.421 13.512 12.659 ;
     RECT  6.144 11.365 6.264 13.139 ;
     RECT  24 8.003 24.312 13.333 ;
     RECT  29.4 8.723 29.712 13.333 ;
     RECT  16.224 10.213 16.248 13.379 ;
     RECT  25.536 9.203 25.56 13.379 ;
     RECT  2.4 11.653 2.904 13.523 ;
     RECT  23.904 13.333 24.312 13.571 ;
     RECT  40.2 2.151 40.512 13.573 ;
     RECT  11.664 12.659 11.88 13.621 ;
     RECT  18.6 9.731 18.912 13.621 ;
     RECT  28.464 13.333 29.712 13.621 ;
     RECT  11.568 13.621 11.88 13.765 ;
     RECT  13.104 12.659 13.512 13.765 ;
     RECT  11.568 13.765 13.512 14.003 ;
     RECT  13.104 14.003 13.512 14.147 ;
     RECT  17.616 13.621 18.912 14.485 ;
     RECT  9.6 14.197 9.624 14.675 ;
     RECT  17.616 14.485 19.512 15.061 ;
     RECT  16.896 15.061 19.512 15.203 ;
     RECT  39.36 13.573 40.512 15.683 ;
     RECT  6.24 13.139 6.264 16.019 ;
     RECT  16.896 15.203 18.912 16.019 ;
     RECT  14.928 15.349 14.952 16.067 ;
     RECT  18.384 16.019 18.912 16.403 ;
     RECT  16.896 16.019 16.92 16.547 ;
     RECT  24 13.571 24.312 16.549 ;
     RECT  11.568 14.003 11.88 16.595 ;
     RECT  28.176 13.621 29.712 16.787 ;
     RECT  18.6 16.403 18.912 16.789 ;
     RECT  0.192 14.869 0.216 16.931 ;
     RECT  28.176 16.787 28.2 16.933 ;
     RECT  27.936 16.933 28.2 16.979 ;
     RECT  18.6 16.789 19.032 17.075 ;
     RECT  27.936 16.979 28.152 17.123 ;
     RECT  27.072 17.317 27.096 17.459 ;
     RECT  39.888 15.683 40.512 17.747 ;
     RECT  34.8 4.115 35.112 17.989 ;
     RECT  28.128 17.123 28.152 18.181 ;
     RECT  29.4 16.787 29.712 18.181 ;
     RECT  24 16.549 24.504 18.515 ;
     RECT  21.84 18.181 21.864 18.803 ;
     RECT  11.712 16.595 11.88 18.851 ;
     RECT  18.6 17.075 18.912 20.149 ;
     RECT  11.712 18.851 11.736 20.197 ;
     RECT  24 18.515 24.312 20.485 ;
     RECT  6.24 19.477 6.264 20.579 ;
     RECT  7.8 10.883 8.112 20.581 ;
     RECT  11.52 20.197 11.736 21.155 ;
     RECT  15.6 19.957 15.624 21.155 ;
     RECT  18.6 20.149 19.176 21.155 ;
     RECT  24 20.485 25.08 21.395 ;
     RECT  37.296 17.605 37.32 21.635 ;
     RECT  28.128 18.181 29.712 21.637 ;
     RECT  34.656 17.989 35.112 21.683 ;
     RECT  28.128 21.637 30.264 21.731 ;
     RECT  4.56 19.765 4.584 22.117 ;
     RECT  4.56 22.117 4.824 22.163 ;
     RECT  28.512 21.731 30.264 22.163 ;
     RECT  18.6 21.155 18.912 22.165 ;
     RECT  34.8 21.683 35.112 22.165 ;
     RECT  28.608 22.163 30.264 22.211 ;
     RECT  7.8 20.581 9 22.259 ;
     RECT  12 21.925 12.024 23.027 ;
     RECT  2.4 13.523 2.712 23.317 ;
     RECT  13.2 14.147 13.512 23.317 ;
     RECT  14.496 19.333 14.52 23.317 ;
     RECT  24 21.395 24.312 23.317 ;
     RECT  18.6 22.165 19.32 23.365 ;
     RECT  28.704 22.211 30.264 23.411 ;
     RECT  22.56 19.333 22.584 23.845 ;
     RECT  24 23.317 24.408 23.845 ;
     RECT  22.56 23.845 24.408 23.891 ;
     RECT  18.6 23.365 19.512 24.085 ;
     RECT  13.2 23.317 14.52 24.131 ;
     RECT  13.2 24.131 13.896 24.515 ;
     RECT  2.4 23.317 2.904 24.659 ;
     RECT  18.096 24.085 19.512 24.659 ;
     RECT  22.56 23.891 24.312 24.659 ;
     RECT  23.04 24.659 24.312 24.899 ;
     RECT  10.704 24.901 10.728 24.949 ;
     RECT  9.792 24.949 10.728 24.997 ;
     RECT  13.2 24.515 13.512 25.045 ;
     RECT  16.56 24.421 16.584 25.139 ;
     RECT  4.8 22.163 4.824 25.621 ;
     RECT  4.8 25.621 5.064 25.667 ;
     RECT  34.8 22.165 35.4 25.715 ;
     RECT  23.328 24.899 24.312 26.005 ;
     RECT  26.784 23.845 26.808 26.243 ;
     RECT  36.432 21.637 36.456 26.243 ;
     RECT  30.816 26.245 30.84 26.341 ;
     RECT  28.704 23.411 29.712 26.387 ;
     RECT  30.816 26.341 31.272 26.387 ;
     RECT  29.4 26.387 29.712 26.581 ;
     RECT  29.4 26.581 29.832 26.723 ;
     RECT  23.328 26.005 24.696 27.107 ;
     RECT  7.8 22.259 8.112 27.205 ;
     RECT  9.792 24.997 10.872 27.205 ;
     RECT  23.328 27.107 24.312 27.301 ;
     RECT  16.272 26.629 16.296 27.395 ;
     RECT  7.8 27.205 10.872 27.445 ;
     RECT  7.8 27.445 11.016 27.877 ;
     RECT  23.232 27.301 24.312 27.971 ;
     RECT  7.8 27.877 11.88 28.405 ;
     RECT  18.096 24.659 18.912 28.453 ;
     RECT  7.8 28.405 11.976 28.837 ;
     RECT  27.888 28.405 27.912 29.075 ;
     RECT  34.8 25.715 35.112 29.077 ;
     RECT  36.144 26.725 36.168 29.077 ;
     RECT  14.592 28.405 14.616 29.123 ;
     RECT  31.248 26.387 31.272 29.123 ;
     RECT  17.328 28.453 18.912 29.651 ;
     RECT  18.192 29.651 18.912 29.653 ;
     RECT  7.008 28.837 11.976 29.699 ;
     RECT  13.104 25.045 13.512 29.893 ;
     RECT  34.8 29.077 36.168 30.035 ;
     RECT  18.192 29.653 19.368 30.083 ;
     RECT  5.04 25.667 5.064 30.275 ;
     RECT  18.6 30.083 19.368 30.275 ;
     RECT  13.104 29.893 13.656 30.371 ;
     RECT  34.8 30.035 35.352 30.611 ;
     RECT  7.344 29.699 11.976 30.803 ;
     RECT  26.736 30.757 26.76 30.947 ;
     RECT  34.8 30.611 35.208 30.995 ;
     RECT  7.344 30.803 11.88 31.379 ;
     RECT  13.104 30.371 13.512 31.475 ;
     RECT  7.8 31.379 11.88 31.523 ;
     RECT  32.304 31.333 32.328 31.955 ;
     RECT  2.4 24.659 2.712 32.409 ;
     RECT  7.8 31.523 11.352 32.409 ;
     RECT  13.2 31.475 13.512 32.409 ;
     RECT  18.6 30.275 18.912 32.409 ;
     RECT  24 27.971 24.312 32.409 ;
     RECT  29.4 26.723 29.712 32.409 ;
     RECT  34.8 30.995 35.112 32.409 ;
     RECT  40.2 17.747 40.512 32.409 ;
     RECT  2.4 32.409 2.52 32.423 ;
     RECT  7.8 32.409 7.92 32.423 ;
     RECT  13.2 32.409 13.32 32.423 ;
     RECT  18.6 32.409 18.72 32.423 ;
     RECT  24 32.409 24.12 32.423 ;
     RECT  29.4 32.409 29.52 32.423 ;
     RECT  34.8 32.409 34.92 32.423 ;
     RECT  40.2 32.409 40.32 32.423 ;
     RECT  9.024 32.409 11.352 33.683 ;
     RECT  9.024 33.683 11.208 34.384 ;
     RECT  9.024 1.187 9.456 2.137 ;
     RECT  10.056 1.859 11.184 2.821 ;
     RECT  7.92 2.137 9.456 2.151 ;
     RECT  8.112 2.151 9.456 2.629 ;
     RECT  11.544 2.725 12.528 3.731 ;
     RECT  27.912 2.821 29.4 3.443 ;
     RECT  13.512 3.301 14.88 6.277 ;
     RECT  14.904 3.347 15.288 3.733 ;
     RECT  11.544 3.731 12.576 5.171 ;
     RECT  14.904 3.733 16.176 4.307 ;
     RECT  2.712 4.261 4.128 5.459 ;
     RECT  14.904 4.307 15.096 5.605 ;
     RECT  23.136 4.643 24 5.605 ;
     RECT  24.504 5.267 25.536 5.843 ;
     RECT  2.712 5.459 4.104 6.421 ;
     RECT  22.488 5.605 24 6.275 ;
     RECT  24.312 5.843 25.536 13.379 ;
     RECT  23.04 6.275 24 6.805 ;
     RECT  13.512 6.277 14.784 7.475 ;
     RECT  12.576 6.323 12.624 7.285 ;
     RECT  2.712 6.421 4.08 7.811 ;
     RECT  11.256 7.285 12.624 7.717 ;
     RECT  29.832 7.381 31.344 7.475 ;
     RECT  13.512 7.475 14.712 8.437 ;
     RECT  11.592 7.717 12.624 7.765 ;
     RECT  11.88 7.907 13.2 12.421 ;
     RECT  13.512 8.437 14.688 10.883 ;
     RECT  4.824 8.485 6 10.067 ;
     RECT  16.392 8.965 17.664 9.155 ;
     RECT  6.024 9.107 6.072 10.261 ;
     RECT  10.008 9.491 11.232 10.453 ;
     RECT  9.744 9.731 9.792 10.165 ;
     RECT  8.616 10.165 9.792 10.883 ;
     RECT  14.712 10.213 16.224 10.883 ;
     RECT  6.144 10.307 6.24 11.365 ;
     RECT  10.152 10.453 11.232 11.027 ;
     RECT  10.008 11.027 11.232 11.699 ;
     RECT  11.88 12.659 13.104 13.765 ;
     RECT  11.88 14.003 13.104 14.147 ;
     RECT  11.88 14.147 13.2 18.851 ;
     RECT  8.112 14.197 9.6 14.675 ;
     RECT  13.512 15.349 14.928 16.067 ;
     RECT  16.92 16.019 18.384 16.403 ;
     RECT  28.2 16.787 29.4 16.979 ;
     RECT  28.152 16.979 29.4 18.181 ;
     RECT  27.936 17.123 28.128 17.317 ;
     RECT  27.096 17.317 28.128 17.459 ;
     RECT  11.736 18.851 13.2 21.155 ;
     RECT  13.512 19.333 14.496 23.317 ;
     RECT  22.584 19.333 24 23.845 ;
     RECT  14.52 19.957 15.6 21.155 ;
     RECT  12 21.155 13.2 21.925 ;
     RECT  18.912 21.155 19.176 22.165 ;
     RECT  35.112 21.637 36.432 22.165 ;
     RECT  12.024 21.925 13.2 23.027 ;
     RECT  35.4 22.165 36.432 25.715 ;
     RECT  16.584 24.421 18.096 25.139 ;
     RECT  35.112 25.715 36.432 26.243 ;
     RECT  35.112 26.243 36.168 26.725 ;
     RECT  29.712 26.245 30.816 26.387 ;
     RECT  29.712 26.387 31.248 26.581 ;
     RECT  29.832 26.581 31.248 26.723 ;
     RECT  35.112 26.725 36.144 29.077 ;
     RECT  11.88 27.877 13.104 28.405 ;
     RECT  11.976 28.405 13.104 30.803 ;
     RECT  13.512 28.405 14.592 29.123 ;
     RECT  27.912 28.405 29.4 29.075 ;
     RECT  13.512 29.123 13.656 29.893 ;
     RECT  11.88 30.803 13.104 31.475 ;
     RECT  11.88 31.475 13.2 31.523 ;
     RECT  7.92 32.409 9.024 32.423 ;
  END
END ot_s81_markov_fold_native
END LIBRARY
